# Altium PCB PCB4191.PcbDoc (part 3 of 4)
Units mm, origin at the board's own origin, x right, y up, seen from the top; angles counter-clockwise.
Board outline 160 x 160 mm, 6 copper layers (Top Layer, IM1 RIS, IM2 Signal, IM3 Signal, IM4 GND, Bottom Layer), stack 1.582 mm thick; 143 components, 121 nets, 430 pads, 4960 vias.

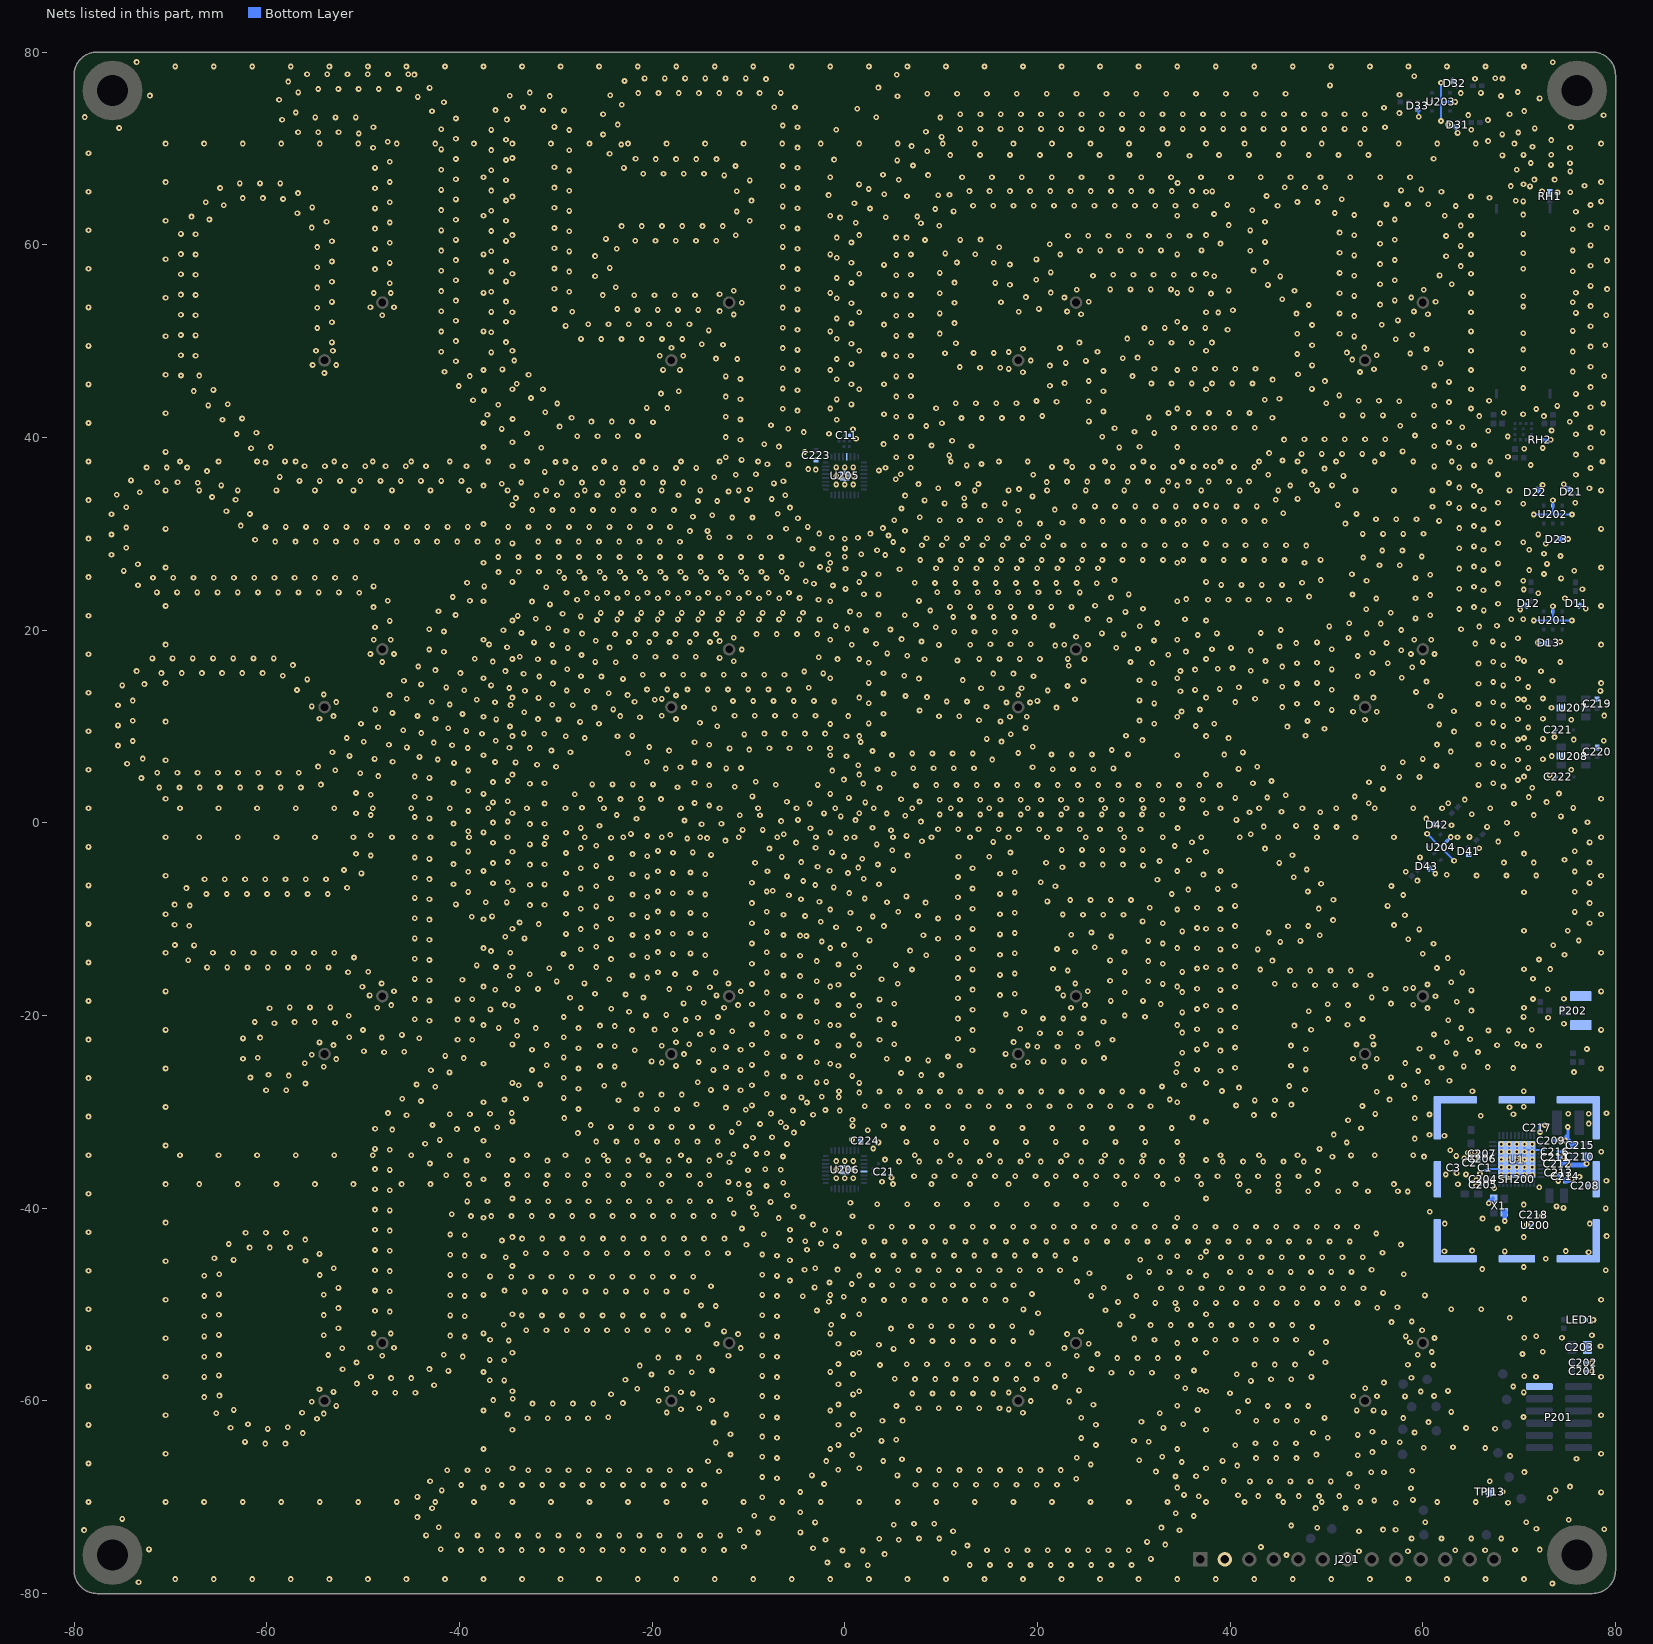
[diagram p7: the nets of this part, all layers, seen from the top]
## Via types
v1: diameter 0.6, hole 0.25, IM4 GND to Bottom Layer, tented bottom, 3930 vias
v2: diameter 0.6, hole 0.25, Top Layer to Bottom Layer, tented both sides, 851 vias
v3: diameter 0.6, hole 0.25, IM4 GND to Bottom Layer, tented both sides, 179 vias

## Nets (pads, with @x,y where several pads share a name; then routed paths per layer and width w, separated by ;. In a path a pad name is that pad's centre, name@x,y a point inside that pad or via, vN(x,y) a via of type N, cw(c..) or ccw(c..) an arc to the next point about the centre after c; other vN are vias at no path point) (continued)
GND: (continued)
  other v1: 0.276,-77.063 2.376,-77.063 12.972,-77.038 15.072,-77.038 17.172,-77.038 19.272,-77.038 21.372,-77.038 23.472,-77.038 25.572,-77.038 27.672,-77.038 29.772,-77.038 -1.804,-76.776 31.774,-76.405 45.849,-76 4.127,-75.903 11.306,-75.76 58.449,-75.616 53.368,-75.606 -0.231,-75.537 1.869,-75.537 14.763,-75.512 16.863,-75.512 18.963,-75.512 21.063,-75.512 23.163,-75.512 25.263,-75.512 27.363,-75.512 29.463,-75.512 63.363,-75.515 66.463,-75.515 -39.84,-75.488 -37.74,-75.488 -35.64,-75.488 -33.54,-75.488 -31.44,-75.488 -29.34,-75.488 -27.24,-75.488 -25.14,-75.488 -23.04,-75.488 -20.94,-75.488 -18.84,-75.488 -16.74,-75.488 -14.64,-75.488 -12.54,-75.488 69.562,-75.45 -41.939,-75.409 -3.289,-75.291 43.186,-75.174 -10.468,-75.148 12.722,-75.018 33.259,-74.921 31.376,-74.645 5.612,-74.418 -2.006,-74.414 3.568,-74.303 7.708,-74.288 9.808,-74.288 58.833,-74.286 61.933,-74.286 65.033,-74.286 68.133,-74.286 -43.464,-73.965 -40.222,-73.962 -38.122,-73.962 -36.022,-73.962 -33.922,-73.962 -31.822,-73.962 -29.722,-73.962 -27.622,-73.962 -25.522,-73.962 -23.422,-73.962 -21.322,-73.962 -19.222,-73.962 -17.122,-73.962 -15.022,-73.962 -12.922,-73.962 -8.983,-73.663 -4.611,-73.66 11.237,-73.533 53.375,-73.529 34.744,-73.436 -10.894,-73.415 55.873,-73.366 71.783,-73.287 32.861,-73.16 49.049,-73.166 -42.147,-73.123 46.351,-72.941 5.086,-72.852 7.184,-72.762 9.284,-72.762 -3.087,-72.614 70.733,-72.597 -7.498,-72.178 -44.363,-72.067 -9.409,-71.93 36.229,-71.951 34.346,-71.675 -4.613,-71.56 -42.837,-71.14 48.87,-71.135 51.97,-71.135 54.966,-70.339 -8.563,-70.008 -44.362,-69.967 36.738,-69.913 42.918,-69.888 45.018,-69.888 47.118,-69.888 49.218,-69.888 51.318,-69.888 40.82,-69.802 35.212,-69.762 -4.613,-69.46 -41.838,-69.293 58.768,-69.061 53.183,-68.922 -39.813,-68.738 -35.613,-68.738 -33.513,-68.738 -31.413,-68.738 -29.313,-68.738 -27.213,-68.738 -25.113,-68.738 -23.013,-68.738 -20.913,-68.738 -18.813,-68.738 -16.713,-68.738 7.326,-68.713 9.426,-68.713 11.526,-68.713 13.626,-68.713 15.726,-68.713 17.826,-68.713 19.926,-68.713 22.026,-68.713 -14.613,-68.701 -2.153,-68.633 42.048,-68.362 44.148,-68.362 46.248,-68.362 48.348,-68.362 50.448,-68.362 -43.04,-68.336 39.326,-68.326 24.033,-68.096 -7.037,-68.029 -8.563,-67.908 34.327,-67.857 36.461,-67.832 5.463,-67.743 -3.415,-67.735 52.388,-67.557 54.642,-67.412 55.96,-67.403 32.293,-67.338 -13.047,-67.302 -41.266,-67.212 -39.166,-67.212 -37.066,-67.212 -32.866,-67.212 -30.766,-67.212 -28.666,-67.212 -26.566,-67.212 -24.466,-67.212 -22.366,-67.212 -20.266,-67.212 -18.166,-67.212 -16.066,-67.212 7.706,-67.187 9.806,-67.187 11.906,-67.187 14.006,-67.187 16.106,-67.187 18.206,-67.187 20.306,-67.187 22.406,-67.187 -0.668,-67.148 40.738,-66.72 25.518,-66.611 34.976,-66.347 -14.184,-66.28 -1.93,-66.25 3.99,-66.247 39.212,-66.229 30.555,-66.159 5.936,-66.057 42.687,-65.938 44.787,-65.938 46.887,-65.938 -7.037,-65.929 24.068,-65.903 -8.563,-65.808 32.946,-65.812 53.237,-65.636 0.779,-65.626 -11.862,-65.568 48.955,-65.574 54.763,-65.315 40.537,-64.601 -0.663,-64.575 26.063,-64.583 -60.16,-64.438 -58.06,-64.438 42.629,-64.412 44.729,-64.412 46.829,-64.412 -13.388,-64.336 55.96,-64.303 -62.252,-64.257 31.538,-64.253 3.812,-64.154 30.012,-64.131 5.338,-64.044 24.537,-63.856 -7.037,-63.829 50.138,-63.839 -8.563,-63.708 0.863,-63.527 53.237,-63.536 -11.862,-63.468 -56.266,-63.346 48.612,-63.302 54.763,-63.215 -59.903,-62.912 33.067,-62.813 -63.747,-62.782 -57.811,-62.731 26.063,-62.483 -0.663,-62.475 -61.946,-62.425 35.131,-62.424 -13.629,-62.25 30.79,-62.18 3.904,-62.056 6.003,-62.052 42.716,-62.063 44.816,-62.063 46.916,-62.063 -54.781,-61.861 -32.94,-61.813 -30.84,-61.813 -28.74,-61.813 -26.64,-61.813 24.537,-61.756 49.796,-61.767 -7.037,-61.729 -24.543,-61.695 -8.563,-61.608 -12.305,-61.416 0.863,-61.427 -35,-61.405 -54.082,-61.32 -65.232,-61.297 32.691,-61.287 -56.326,-61.247 18.484,-61.237 -18.484,-61.213 55.96,-61.203 40.832,-61.136 53.137,-60.991 54.887,-60.991 -63.431,-60.94 36.616,-60.939 17.009,-60.887 -17.009,-60.863 -15.114,-60.765 7.661,-60.763 9.761,-60.763 11.861,-60.763 13.961,-60.763 16.061,-60.763 -52.792,-60.524 5.356,-60.539 43.895,-60.537 45.995,-60.537 48.095,-60.537 25.804,-60.399 -0.663,-60.375 -32.417,-60.287 -30.317,-60.287 -28.217,-60.287 -26.117,-60.287 -23.032,-60.237 -55.32,-60.082 23.302,-60.057 19.309,-60.012 41.862,-60.008 -19.309,-59.988 -36.485,-59.92 -13.79,-59.931 -34.457,-59.789 -66.488,-59.615 -7.037,-59.629 -8.563,-59.508 52.787,-59.516 55.237,-59.516 -64.916,-59.455 -24.26,-59.306 0.863,-59.327 -15.772,-59.237 7.003,-59.237 9.103,-59.237 11.203,-59.237 13.303,-59.237 15.403,-59.237 39.987,-59.214 -48.772,-59.163 -46.672,-59.163 -44.572,-59.163 17.009,-59.137 -17.009,-59.113 -53.075,-59.075 62.615,-58.966 24.319,-58.915 36.863,-58.854 -54.524,-58.792 18.484,-58.787 -21.547,-58.752 -18.484,-58.763 35.337,-58.689 54.012,-58.691 21.817,-58.572 -42.624,-58.379 -0.663,-58.275 -50.644,-58.211 55.96,-58.103 42.152,-57.928 -35.337,-57.882 -36.863,-57.854 -22.775,-57.821 44.245,-57.763 46.345,-57.763 7.29,-57.738 9.39,-57.738 11.49,-57.738 13.59,-57.738 15.69,-57.738 17.79,-57.738 19.89,-57.738 5.19,-57.702 -47.094,-57.637 -44.994,-57.637 58.809,-57.613 -7.037,-57.529 -66.488,-57.515 -49.19,-57.506 48.43,-57.514 22.834,-57.43 -8.563,-57.408 -64.962,-57.355 -20.063,-57.267 0.863,-57.227 40.687,-57.234 27.677,-57.088 29.777,-57.088 31.877,-57.088 -17.975,-57.038 -15.875,-57.038 -41.139,-56.894 -13.784,-56.847 36.25,-56.845 -52.129,-56.726 -43.111,-56.707 25.614,-56.694 -21.29,-56.336 3.65,-56.274 58.453,-56.26 61.069,-56.279 42.535,-56.237 44.635,-56.237 46.735,-56.237 6.423,-56.212 8.523,-56.212 10.623,-56.212 12.723,-56.212 14.823,-56.212 16.923,-56.212 19.023,-56.212 21.123,-56.212 -0.663,-56.175 -50.675,-56.021 49.882,-55.997 -35.337,-55.782 -36.863,-55.754 28.288,-55.562 30.388,-55.562 32.488,-55.562 34.588,-55.562 -19.359,-55.512 -17.259,-55.512 -15.159,-55.512 -7.037,-55.429 -66.488,-55.415 -39.656,-55.408 -12.082,-55.32 24.082,-55.32 -48.012,-55.309 -8.563,-55.308 -64.962,-55.255 -53.614,-55.241 -41.626,-55.222 59.476,-55.208 26.229,-55.149 0.863,-55.127 48.448,-55.023 60.925,-54.925 5.063,-54.612 -52.16,-54.536 -10.792,-54.524 22.792,-54.524 -49.237,-54.484 -46.787,-54.484 3.537,-54.177 -13.32,-54.082 -0.663,-54.075 25.32,-54.082 49.936,-53.897 58.68,-53.918 6.995,-53.788 9.095,-53.788 11.195,-53.788 13.295,-53.788 15.395,-53.788 17.495,-53.788 -34.878,-53.732 -36.819,-53.655 32.148,-53.663 36.348,-53.663 38.448,-53.663 40.548,-53.663 42.648,-53.663 44.748,-53.663 46.848,-53.663 30.052,-53.534 61.208,-53.476 74.438,-53.46 -66.488,-53.315 -39.437,-53.319 -7.037,-53.329 58.227,-53.307 71.78,-53.303 -40.963,-53.229 -54.088,-53.195 -8.563,-53.208 -64.962,-53.155 -11.075,-53.075 23.075,-53.075 -48.887,-53.009 -47.137,-53.009 0.863,-53.027 19.4,-52.904 -12.524,-52.792 24.524,-52.792 59.918,-52.68 -33.071,-52.663 -30.971,-52.663 -28.871,-52.663 -26.771,-52.663 -24.671,-52.663 -22.571,-52.663 -20.471,-52.663 -18.371,-52.663 -16.271,-52.663 4.798,-52.498 -52.562,-52.475 48.528,-52.339 6.884,-52.262 8.984,-52.262 11.084,-52.262 13.184,-52.262 15.284,-52.262 17.384,-52.262 31.738,-52.137 33.838,-52.137 35.938,-52.137 38.038,-52.137 40.138,-52.137 42.238,-52.137 44.338,-52.137 46.438,-52.137 -35.406,-52.101 -1.405,-52.111 28.543,-52.073 -14.258,-52.063 56.742,-51.822 58.841,-51.762 69.031,-51.378 -7.037,-51.229 -66.488,-51.215 -39.437,-51.219 29.849,-51.22 -0.162,-51.195 -40.963,-51.129 -33.541,-51.137 -31.441,-51.137 -29.341,-51.137 -27.241,-51.137 -25.141,-51.137 -23.041,-51.137 -20.941,-51.137 -18.841,-51.137 -16.741,-51.137 -8.563,-51.108 -54.088,-51.095 -64.962,-51.055 20.063,-50.912 -47.237,-50.731 -48.763,-50.647 -2.89,-50.626 27.058,-50.588 18.537,-50.506 62.958,-50.498 66.058,-50.498 -52.562,-50.375 55.257,-50.337 57.357,-50.277 -13.387,-50.152 -14.913,-50.102 32.217,-49.838 34.317,-49.838 36.417,-49.838 38.517,-49.838 40.617,-49.838 42.717,-49.838 44.817,-49.838 46.917,-49.838 49.017,-49.838 51.117,-49.838 53.217,-49.838 28.364,-49.735 -1.647,-49.71 1.973,-49.538 4.073,-49.538 6.173,-49.538 8.273,-49.538 10.373,-49.538 12.473,-49.538 14.573,-49.538 16.673,-49.538 -0.1,-49.204 -39.437,-49.119 -7.037,-49.129 -4.375,-49.141 30.243,-49.123 -66.488,-49.115 25.574,-49.103 60.212,-49.06 -40.963,-49.029 -54.088,-48.995 -8.563,-49.008 -64.962,-48.955 19.418,-48.913 55.872,-48.792 -33.219,-48.638 -31.119,-48.638 -29.019,-48.638 -26.919,-48.638 -24.819,-48.638 -22.719,-48.638 -20.619,-48.638 -18.519,-48.638 -16.419,-48.638 -47.237,-48.631 -48.763,-48.547 -35.318,-48.557 32.827,-48.312 34.927,-48.312 37.027,-48.312 39.127,-48.312 41.227,-48.312 43.327,-48.312 45.427,-48.312 47.527,-48.312 49.627,-48.312 51.727,-48.312 53.827,-48.312 -52.562,-48.275 26.879,-48.25 -3.132,-48.225 -13.884,-48.112 2.821,-48.012 4.921,-48.012 7.021,-48.012 9.121,-48.012 11.221,-48.012 13.321,-48.012 15.421,-48.012 17.521,-48.012 0.726,-47.872 -1.585,-47.719 24.089,-47.618 -5.698,-47.51 29.562,-47.136 -34.63,-47.112 -32.53,-47.112 -30.43,-47.112 -28.33,-47.112 -26.23,-47.112 -24.13,-47.112 -22.03,-47.112 -19.93,-47.112 -17.83,-47.112 -15.73,-47.112 -36.812,-47.082 -66.488,-47.015 -39.437,-47.019 -7.037,-47.029 -54.495,-46.935 -40.963,-46.929 -8.563,-46.908 58.02,-46.868 -64.926,-46.856 25.394,-46.765 31.592,-46.613 33.692,-46.613 35.792,-46.613 39.992,-46.613 42.092,-46.613 44.192,-46.613 46.292,-46.613 48.392,-46.613 50.492,-46.613 52.592,-46.613 -47.237,-46.531 -48.763,-46.447 3.451,-46.438 5.551,-46.438 7.651,-46.438 9.751,-46.438 11.851,-46.438 13.951,-46.438 16.051,-46.438 18.151,-46.438 20.251,-46.438 22.351,-46.438 -4.173,-46.401 -0.748,-46.376 54.681,-46.396 -53.04,-46.23 -3.07,-46.234 -55.98,-45.45 -5.7,-45.41 -63.441,-45.371 30.669,-45.352 23.909,-45.28 72.752,-45.249 -65.43,-45.201 -35.181,-45.085 32.752,-45.087 36.952,-45.087 39.052,-45.087 41.152,-45.087 43.252,-45.087 45.352,-45.087 47.452,-45.087 49.552,-45.087 51.652,-45.087 53.752,-45.087 -7.037,-44.929 -39.437,-44.919 0.842,-44.912 2.942,-44.912 5.042,-44.912 7.142,-44.912 9.242,-44.912 11.342,-44.912 13.442,-44.912 15.542,-44.912 17.642,-44.912 19.742,-44.912 21.842,-44.912 -40.963,-44.829 -8.563,-44.808 -54.525,-44.745 -33.118,-44.688 -31.018,-44.688 -28.918,-44.688 -26.818,-44.688 -24.718,-44.688 -22.618,-44.688 -20.518,-44.688 -18.418,-44.688 -16.318,-44.688 -14.218,-44.688 -12.119,-44.688 55.813,-44.627 -47.237,-44.431 -48.763,-44.347 -3.924,-44.316 -61.778,-44.088 -59.678,-44.088 -57.578,-44.088 -0.925,-43.95 -10.214,-43.804 57.727,-43.782 -63.945,-43.716 2.02,-43.463 4.12,-43.463 6.22,-43.463 8.32,-43.463 10.42,-43.463 12.52,-43.463 14.62,-43.463 16.72,-43.463 18.82,-43.463 20.92,-43.463 23.02,-43.463 25.12,-43.463 27.22,-43.463 29.32,-43.463 31.42,-43.463 33.52,-43.463 35.62,-43.463 37.72,-43.463 39.82,-43.463 41.92,-43.463 44.02,-43.463 46.12,-43.463 48.22,-43.463 50.32,-43.463 52.42,-43.463 -35.591,-43.353 -5.7,-43.31 -56.01,-43.26 -33.5,-43.162 -31.4,-43.162 -29.3,-43.162 -27.2,-43.162 -25.1,-43.162 -23,-43.162 -20.9,-43.162 -18.8,-43.162 -16.7,-43.162 -14.6,-43.162 -12.5,-43.162 -39.437,-42.819 -40.963,-42.729 -8.417,-42.713 55.161,-42.631 -62.191,-42.562 -60.091,-42.562 -57.991,-42.562 -47.237,-42.331 -48.763,-42.247 -10.681,-42.112 67.747,-42.114 2.779,-41.937 4.879,-41.937 6.979,-41.937 9.079,-41.937 11.179,-41.937 13.279,-41.937 15.379,-41.937 17.479,-41.937 19.579,-41.937 21.679,-41.937 23.779,-41.937 25.879,-41.937 27.979,-41.937 30.079,-41.937 32.179,-41.937 34.279,-41.937 36.379,-41.937 38.479,-41.937 40.579,-41.937 42.679,-41.937 44.779,-41.937 46.879,-41.937 48.979,-41.937 51.079,-41.937 53.179,-41.937 -38.797,-40.819 -36.697,-40.819 -34.597,-40.819 -32.497,-40.819 -30.397,-40.819 -28.297,-40.819 -26.197,-40.819 -24.097,-40.819 -21.997,-40.819 -19.897,-40.819 -17.797,-40.819 -15.697,-40.819 -13.597,-40.819 -40.806,-40.635 -9.196,-40.627 -11.515,-40.544 60.716,-40.361 -47.237,-40.231 -48.763,-40.147 -9.518,-39.895 3.378,-39.594 6.478,-39.594 9.578,-39.594 12.678,-39.594 15.778,-39.594 18.878,-39.594 21.978,-39.594 25.078,-39.594 28.178,-39.594 31.278,-39.594 -39.19,-39.294 -37.09,-39.293 -32.89,-39.293 -30.79,-39.293 -28.69,-39.293 -26.59,-39.293 -24.49,-39.293 -22.39,-39.293 -20.29,-39.293 -18.19,-39.293 -16.09,-39.293 -13.99,-39.293 -11.902,-39.065 -9.905,-38.416 58.43,-38.267 41.911,-38.246 45.011,-38.246 48.111,-38.246 51.211,-38.246 54.311,-38.246 57.411,-38.246 -47.237,-38.131 -48.763,-38.047 -10.001,-37.6 -12.076,-37.278 7.197,-36.695 9.297,-36.695 11.397,-36.695 13.497,-36.695 15.597,-36.695 17.697,-36.695 19.797,-36.695 21.897,-36.695 23.997,-36.695 26.097,-36.695 28.197,-36.695 30.297,-36.695 32.397,-36.695 36.597,-36.695 38.697,-36.695 40.797,-36.695 42.897,-36.695 44.997,-36.695 47.097,-36.695 -41.36,-36.588 -39.26,-36.588 -35.06,-36.588 -32.96,-36.588 -30.86,-36.588 -28.76,-36.588 -26.66,-36.588 -24.56,-36.588 -22.46,-36.588 -20.36,-36.588 -18.26,-36.588 -16.16,-36.588 -14.06,-36.588 49.126,-36.154 -10.05,-36.073 -47.237,-36.031 -48.763,-35.947 -43.066,-35.364 -11.977,-35.24 5.637,-35.168 7.737,-35.168 9.837,-35.168 11.937,-35.168 14.037,-35.168 16.137,-35.168 18.237,-35.168 20.337,-35.168 22.437,-35.168 24.537,-35.168 26.637,-35.168 28.737,-35.168 30.837,-35.168 32.937,-35.168 35.037,-35.168 39.237,-35.168 41.337,-35.168 43.437,-35.168 45.537,-35.168 47.637,-35.168 -39.27,-35.062 -30.87,-35.062 -26.67,-35.062 -24.57,-35.062 -22.47,-35.062 -20.37,-35.062 -18.27,-35.062 -16.17,-35.062 -14.07,-35.062 50.611,-34.669 60.119,-34.644 -11.567,-34.413 -47.237,-33.931 -48.763,-33.847 49.271,-33.849 -10.254,-33.566 -43.563,-33.324 3.5,-33.175 52.096,-33.184 6.396,-33.123 9.496,-33.123 12.596,-33.123 15.696,-33.123 18.796,-33.123 21.896,-33.123 24.996,-33.123 28.096,-33.123 31.196,-33.123 -25.797,-33.088 -23.697,-33.088 -21.597,-33.088 -19.497,-33.088 -17.397,-33.088 -15.297,-33.088 -13.197,-33.088 -42.037,-32.917 59.164,-32.774 -9.533,-32.682 50.756,-32.364 60.69,-32.375 -27.701,-32.203 -11.739,-32.081 2.391,-31.917 -46.969,-31.848 -40.266,-31.788 -38.166,-31.788 -48.753,-31.747 53.581,-31.699 6.038,-31.677 9.138,-31.677 12.238,-31.677 15.338,-31.677 18.438,-31.677 21.538,-31.677 24.638,-31.677 27.738,-31.677 30.838,-31.677 33.938,-31.677 -36.074,-31.607 -6.112,-31.59 -24.274,-31.562 -22.174,-31.562 -20.074,-31.562 -17.974,-31.562 -15.874,-31.562 -13.774,-31.562 4.06,-31.447 -42.798,-31.368 -26.366,-31.38 -8.79,-31.266 -11.018,-31.197 52.241,-30.879 0.785,-30.819 -29.118,-30.653 59.164,-30.674 36.09,-30.595 66.011,-30.408 -45.484,-30.363 42.461,-30.338 44.561,-30.338 60.69,-30.275 -41.013,-30.262 -38.913,-30.262 -36.813,-30.209 55.066,-30.214 -7.668,-30.18 -47.411,-30.132 -34.578,-30.133 -10.275,-29.781 -21.619,-29.738 -19.519,-29.738 -17.419,-29.738 -27.637,-29.708 -12.338,-29.563 4.445,-29.413 6.545,-29.413 8.645,-29.413 10.745,-29.413 12.845,-29.413 14.945,-29.413 17.045,-29.413 19.145,-29.413 21.245,-29.413 23.345,-29.413 25.445,-29.413 27.545,-29.413 29.645,-29.413 31.745,-29.413 53.726,-29.394 40.612,-29.342 -9.638,-29.332 46.356,-29.249 -15.385,-29.215 -43.999,-28.878 42.545,-28.812 44.645,-28.801 -23.492,-28.788 -35.328,-28.724 33.729,-28.725 56.551,-28.729 -45.926,-28.647 -33.093,-28.648 59.164,-28.574 -29.163,-28.554 -4.503,-28.503 -6.362,-28.448 -21.117,-28.212 -19.017,-28.212 -16.917,-28.212 -8.112,-28.128 1.497,-28.002 3.594,-27.887 5.694,-27.887 7.794,-27.887 9.894,-27.887 11.994,-27.887 14.094,-27.887 16.194,-27.887 18.294,-27.887 20.394,-27.887 22.494,-27.887 24.594,-27.887 26.694,-27.887 28.794,-27.887 30.894,-27.887 55.211,-27.909 -0.598,-27.863 65.141,-27.87 39.144,-27.84 -60.064,-27.761 -57.964,-27.763 -10.812,-27.751 -13.9,-27.73 47.782,-27.707 -27.637,-27.608 40.916,-27.486 -12.338,-27.463 -42.514,-27.393 32.929,-27.367 -24.977,-27.303 46.13,-27.316 -33.843,-27.239 -9.638,-27.232 35.214,-27.24 58.035,-27.244 -22.944,-27.176 -44.441,-27.162 -31.608,-27.163 -55.984,-27.063 -2.911,-26.951 -15.256,-26.927 -1.918,-26.895 60.454,-26.917 62.757,-26.772 -29.163,-26.454 -61.693,-26.436 56.696,-26.424 -4.636,-26.407 -6.362,-26.348 0.778,-26.276 -57.714,-26.237 7.936,-26.188 10.036,-26.188 -59.813,-26.158 -8.112,-26.028 5.847,-25.973 -41.029,-25.908 34.413,-25.882 75.686,-25.879 59.52,-25.759 38.987,-25.746 -42.956,-25.677 -32.463,-25.656 -10.812,-25.651 -13.637,-25.646 36.554,-25.623 47.838,-25.608 -27.637,-25.508 69.39,-25.458 40.513,-25.425 61.938,-25.432 -12.338,-25.363 66.726,-25.36 -54.082,-25.32 -23.887,-25.3 53.988,-25.309 64.242,-25.287 -25.413,-25.249 -17.516,-25.237 11.903,-25.227 46.312,-25.224 -0.663,-25.211 17.516,-25.213 -30.937,-25.173 -9.638,-25.132 -56.044,-24.964 58.181,-24.94 -18.991,-24.887 18.991,-24.863 -2.911,-24.851 -15.163,-24.829 -20.055,-24.763 20.635,-24.763 22.735,-24.763 24.835,-24.763 8.653,-24.662 -52.792,-24.524 6.558,-24.528 -62.463,-24.482 4.36,-24.49 52.763,-24.484 55.213,-24.484 -39.544,-24.424 26.907,-24.423 -60.937,-24.384 -29.163,-24.354 -4.636,-24.307 10.714,-24.257 61.005,-24.274 -6.362,-24.248 -41.471,-24.192 0.863,-24.178 -55.32,-24.082 -16.691,-24.012 16.691,-23.988 -8.112,-23.928 63.423,-23.947 35.037,-23.877 -47.818,-23.813 65.727,-23.803 -45.718,-23.772 -49.915,-23.706 38.987,-23.646 -21.804,-23.601 13.25,-23.616 -32.463,-23.556 -13.657,-23.547 -10.812,-23.551 36.563,-23.523 47.838,-23.508 59.666,-23.455 -27.637,-23.408 40.513,-23.325 -12.338,-23.263 19.977,-23.237 22.077,-23.237 24.177,-23.237 -23.887,-23.2 -25.413,-23.149 -18.991,-23.137 -0.663,-23.111 18.991,-23.113 46.312,-23.124 67.702,-23.088 -53.075,-23.075 -30.937,-23.073 -9.638,-23.032 53.113,-23.009 54.863,-23.009 -16.153,-22.976 5.138,-22.98 69.796,-22.939 26.253,-22.918 -54.524,-22.792 -17.516,-22.787 62.49,-22.789 17.516,-22.763 -2.911,-22.751 -40.188,-22.529 3.612,-22.528 -38.662,-22.518 27.788,-22.516 64.908,-22.462 11.737,-22.423 -62.463,-22.382 -44.16,-22.364 -60.693,-22.298 -48.058,-22.287 -51.429,-22.251 -29.163,-22.254 -4.636,-22.207 54.763,-22.198 -6.362,-22.148 -33.989,-22.113 0.863,-22.078 -45.975,-22.02 61.151,-21.97 -15.021,-21.95 -8.112,-21.828 20.251,-21.838 22.351,-21.838 24.451,-21.838 35.037,-21.777 -13.761,-21.719 -11.681,-21.639 66.805,-21.562 68.905,-21.562 38.987,-21.546 -50.009,-21.511 -22.082,-21.519 13.263,-21.516 -17.638,-21.492 -19.738,-21.463 48.396,-21.483 71.3,-21.472 36.563,-21.423 18.202,-21.381 -32.082,-21.313 -27.637,-21.308 -35.919,-21.285 63.975,-21.304 40.513,-21.225 -23.871,-21.1 46.667,-21.054 -25.413,-21.049 -0.663,-21.011 52.185,-20.964 -9.638,-20.932 5.138,-20.88 -59.209,-20.813 -52.914,-20.766 -61.234,-20.68 -57.112,-20.688 -55.012,-20.688 -2.911,-20.651 26.845,-20.64 -34.053,-20.587 -43.112,-20.545 62.636,-20.485 -16.506,-20.465 -40.188,-20.429 -38.662,-20.418 3.612,-20.428 -44.638,-20.4 50.172,-20.363 53.742,-20.363 11.737,-20.323 20.571,-20.312 22.671,-20.312 24.771,-20.312 73.001,-20.242 -15.246,-20.234 -29.163,-20.154 -13.166,-20.154 70.461,-20.152 31.157,-20.137 -4.636,-20.107 -6.362,-20.048 -51.494,-20.026 -20.638,-19.995 29.062,-19.999 0.863,-19.978 -18.538,-19.937 16.717,-19.896 -8.112,-19.728 35.037,-19.677 -22.386,-19.615 18.591,-19.611 48.151,-19.569 65.038,-19.493 38.987,-19.446 13.263,-19.416 -36.788,-19.374 -24.238,-19.309 36.563,-19.323 -59.707,-19.238 60.484,-19.237 -48.524,-19.208 -27.415,-19.22 -12.524,-19.208 23.476,-19.208 -57.608,-19.162 -55.508,-19.162 -53.408,-19.162 40.513,-19.125 -47.075,-18.925 -11.075,-18.925 24.925,-18.925 -0.663,-18.911 52.218,-18.918 -35.262,-18.87 59.009,-18.887 -9.638,-18.832 50.12,-18.837 32.789,-18.815 5.138,-18.78 -16.731,-18.749 56.694,-18.763 -14.651,-18.669 63.512,-18.576 -2.911,-18.551 27.605,-18.487 30.957,-18.489 -43.112,-18.445 -40.188,-18.329 -38.662,-18.318 3.612,-18.328 -44.638,-18.3 71.432,-18.289 11.737,-18.223 -28.512,-18.157 -20.901,-18.13 54.694,-18.123 -4.636,-18.007 61.309,-18.012 -6.362,-17.948 -49.32,-17.918 -13.32,-17.918 22.68,-17.918 0.863,-17.878 16.112,-17.885 -22.753,-17.824 -25.93,-17.735 17.638,-17.74 -8.112,-17.628 29.063,-17.58 35.037,-17.577 -46.792,-17.476 -10.792,-17.476 25.208,-17.476 65.038,-17.393 38.987,-17.346 -36.289,-17.334 13.263,-17.316 72.959,-17.269 -18.216,-17.264 -33.939,-17.238 -31.839,-17.238 36.563,-17.223 56.118,-17.237 58.218,-17.237 22.117,-17.197 -16.136,-17.185 59.009,-17.137 -14.005,-17.075 40.513,-17.025 -50.071,-17.008 46.714,-16.863 48.814,-16.863 50.914,-16.863 53.014,-16.863 -0.663,-16.811 60.484,-16.787 -9.638,-16.732 5.494,-16.711 33.013,-16.727 44.62,-16.696 -48.082,-16.68 -27.027,-16.672 -12.082,-16.68 23.918,-16.68 62.949,-16.553 -29.887,-16.466 31.487,-16.457 -2.911,-16.451 27.537,-16.388 -43.112,-16.345 -39.693,-16.289 -24.453,-16.242 3.817,-16.238 -44.638,-16.2 71.432,-16.189 11.737,-16.123 -20.512,-16.067 -4.636,-15.907 -34.787,-15.866 -22.038,-15.849 -6.362,-15.848 54.559,-15.83 0.863,-15.778 16.112,-15.785 -32.692,-15.712 -17.621,-15.7 17.638,-15.64 -15.49,-15.59 -51.556,-15.523 -19.388,-15.522 -13.391,-15.53 -8.112,-15.528 64.079,-15.525 29.063,-15.48 35.037,-15.477 -49.457,-15.463 23.138,-15.335 46.218,-15.337 48.318,-15.337 50.418,-15.337 52.518,-15.337 38.987,-15.246 6.979,-15.226 13.263,-15.216 43.121,-15.226 73.219,-15.185 21.612,-15.159 36.563,-15.123 -30.683,-15.103 61.464,-15.068 -66.193,-15.013 -64.093,-15.013 -61.993,-15.013 -59.893,-15.013 -57.793,-15.013 -55.693,-15.013 -53.593,-15.013 -36.213,-14.967 -28.402,-14.981 -25.788,-14.977 40.513,-14.925 -38.208,-14.804 5.297,-14.748 -0.663,-14.711 -9.638,-14.632 33.013,-14.627 -2.911,-14.351 31.487,-14.357 44.388,-14.306 -68.158,-14.271 27.537,-14.288 -43.112,-14.245 72.06,-14.185 -24.262,-14.151 -44.638,-14.1 11.737,-14.023 62.595,-14.04 -50.942,-13.978 -20.512,-13.967 -4.636,-13.807 -22.038,-13.749 -14.487,-13.739 -6.362,-13.748 8.464,-13.741 1.089,-13.69 74.704,-13.7 16.112,-13.685 -29.198,-13.618 -17.862,-13.613 59.979,-13.583 -16.013,-13.556 17.638,-13.54 -65.584,-13.487 -63.484,-13.487 -61.384,-13.487 -59.284,-13.487 -57.184,-13.487 -55.084,-13.487 -52.984,-13.487 -34.728,-13.482 -19.388,-13.422 -8.112,-13.428 23.901,-13.378 29.035,-13.381 -36.723,-13.319 6.782,-13.263 -27.412,-13.129 38.987,-13.146 42.862,-13.142 13.263,-13.116 22.022,-13.099 36.563,-13.023 25.949,-12.913 -25.788,-12.877 40.513,-12.825 -67.542,-12.729 73.545,-12.701 -69.536,-12.687 -0.074,-12.695 61.11,-12.555 -9.638,-12.532 33.013,-12.527 45.189,-12.365 -2.388,-12.317 31.487,-12.257 47.287,-12.263 76.189,-12.215 2.574,-12.205 -43.112,-12.145 58.494,-12.098 -24.262,-12.051 9.688,-12.035 -44.638,-12 -33.243,-11.997 11.737,-11.923 -20.512,-11.867 -35.238,-11.834 27.653,-11.799 -3.983,-11.754 -4.636,-11.707 8.162,-11.68 49.303,-11.676 -22.038,-11.649 -14.487,-11.639 -6.362,-11.648 23.507,-11.614 16.112,-11.585 -28.938,-11.534 -17.862,-11.513 -16.013,-11.456 17.638,-11.44 25.594,-11.387 44.011,-11.384 -8.112,-11.328 -19.388,-11.322 35.037,-11.277 75.03,-11.216 59.625,-11.07 38.987,-11.046 -27.412,-11.029 13.263,-11.016 36.563,-10.923 -0.903,-10.832 -25.788,-10.777 4.059,-10.72 40.513,-10.725 46.009,-10.737 48.109,-10.712 -68.037,-10.688 57.009,-10.613 -69.563,-10.587 -31.758,-10.513 77.304,-10.436 -9.638,-10.432 32.999,-10.427 -33.753,-10.349 -2.498,-10.269 30.909,-10.238 50.685,-10.094 -43.112,-10.045 -24.262,-9.951 9.688,-9.935 -44.638,-9.9 11.737,-9.823 -38.71,-9.763 -20.512,-9.767 2.895,-9.725 -36.61,-9.714 -4.118,-9.672 7.601,-9.656 58.14,-9.585 -22.038,-9.549 -6.362,-9.548 -14.487,-9.539 24.729,-9.538 26.829,-9.538 28.929,-9.538 22.629,-9.519 16.112,-9.485 -28.938,-9.434 -17.862,-9.413 -16.013,-9.356 0.582,-9.348 17.638,-9.34 75.778,-9.253 -19.388,-9.222 -8.112,-9.228 5.544,-9.235 38.987,-8.946 -27.412,-8.929 13.263,-8.916 49.187,-8.91 31.649,-8.819 36.563,-8.823 -25.788,-8.677 40.513,-8.625 56.337,-8.624 -67.984,-8.588 -32.688,-8.539 -69.563,-8.487 -31.162,-8.499 -40.362,-8.467 -9.638,-8.332 77.304,-8.336 8.389,-8.285 -35.092,-8.263 -37.276,-8.237 4.38,-8.24 -2.633,-8.187 21.029,-8.159 23.41,-8.012 25.51,-8.012 27.61,-8.012 29.71,-8.012 50.713,-7.995 -43.112,-7.945 -4.547,-7.942 -24.262,-7.851 2.067,-7.863 -44.638,-7.8 11.737,-7.723 -20.512,-7.667 6.392,-7.637 -5.796,-7.526 57.964,-7.493 -22.038,-7.449 -14.487,-7.439 -66.26,-7.388 -64.161,-7.388 -62.061,-7.388 -59.961,-7.388 -57.861,-7.388 -55.761,-7.388 -53.661,-7.388 33.935,-7.389 16.112,-7.385 -28.938,-7.334 -17.862,-7.313 0.471,-7.299 -16.013,-7.256 17.638,-7.24 -39.087,-7.174 75.778,-7.153 -19.388,-7.122 -8.112,-7.128 48.074,-7.129 -7.482,-7.052 35.641,-6.936 38.71,-6.865 -27.412,-6.829 13.263,-6.816 -68.337,-6.782 -51.662,-6.742 -1.148,-6.702 -25.788,-6.577 21.863,-6.591 56.736,-6.562 40.44,-6.527 -3.062,-6.457 -32.688,-6.439 -31.162,-6.399 -40.613,-6.383 3.552,-6.378 49.434,-6.329 -36.513,-6.28 -9.638,-6.232 77.304,-6.236 20.337,-6.176 -34.987,-6.166 -4.311,-6.041 59.437,-5.996 32.45,-5.904 -66.449,-5.862 -64.349,-5.862 -62.249,-5.862 -60.149,-5.862 -58.049,-5.862 -55.949,-5.862 -53.849,-5.862 -43.112,-5.845 1.956,-5.814 -24.262,-5.751 -44.638,-5.7 46.589,-5.644 11.737,-5.623 -20.512,-5.567 -5.997,-5.567 65.581,-5.469 68.681,-5.469 71.781,-5.469 62.482,-5.384 37.225,-5.38 -22.038,-5.349 -14.487,-5.339 16.112,-5.285 -50.178,-5.257 -28.938,-5.234 -17.862,-5.213 0.337,-5.217 -16.013,-5.156 17.638,-5.14 58.221,-5.077 -39.087,-5.074 75.778,-5.053 -8.025,-5.029 -19.388,-5.022 39.001,-4.997 -1.577,-4.972 -51.981,-4.902 5.037,-4.893 47.949,-4.844 -27.412,-4.729 13.263,-4.716 22.585,-4.619 -2.826,-4.556 -25.788,-4.477 30.965,-4.419 -32.688,-4.339 3.441,-4.329 24.666,-4.338 26.766,-4.338 28.866,-4.338 -31.162,-4.299 -40.613,-4.283 -36.513,-4.18 -9.312,-4.157 20.894,-4.151 45.104,-4.159 77.304,-4.136 68.417,-4.131 71.517,-4.131 -34.987,-4.066 -4.512,-4.082 32.671,-3.966 35.74,-3.895 74.701,-3.843 -43.112,-3.745 1.822,-3.733 -24.262,-3.651 -44.638,-3.6 59.706,-3.592 -6.54,-3.545 11.811,-3.524 14.985,-3.513 -0.092,-3.488 -20.512,-3.467 6.522,-3.408 -49.212,-3.392 46.464,-3.36 -13.875,-3.33 -22.038,-3.249 -50.738,-3.21 -28.938,-3.134 -17.834,-3.114 -15.774,-3.07 -1.342,-3.071 17.192,-3.088 -39.087,-2.974 75.778,-2.953 -19.388,-2.922 4.926,-2.844 22.517,-2.818 24.617,-2.812 26.717,-2.812 28.817,-2.812 30.917,-2.812 -7.827,-2.672 43.619,-2.674 65.836,-2.637 -27.412,-2.629 -3.027,-2.598 34.255,-2.41 -25.788,-2.377 -32.688,-2.239 3.307,-2.248 -40.613,-2.183 -31.162,-2.199 -36.513,-2.08 -5.055,-2.06 77.304,-2.036 36.032,-2.027 15.404,-1.987 67.821,-1.952 8.007,-1.923 -12.39,-1.845 -16.349,-1.629 -14.289,-1.585 0.143,-1.586 -24.262,-1.551 -44.638,-1.5 64.846,-1.468 -20.512,-1.367 6.411,-1.359 -49.212,-1.292 -18.124,-1.245 -6.342,-1.187 42.134,-1.189 -22.199,-1.155 69.752,-1.127 -28.938,-1.034 -39.087,-0.874 75.778,-0.853 4.792,-0.763 -10.605,-0.738 -8.505,-0.738 9.687,-0.663 11.787,-0.663 13.887,-0.663 15.987,-0.663 18.087,-0.663 20.187,-0.663 22.287,-0.663 24.387,-0.663 26.487,-0.663 28.587,-0.663 30.687,-0.663 -3.57,-0.575 -27.412,-0.529 34.547,-0.542 2.878,-0.518 48.941,-0.438 51.041,-0.438 66.669,-0.426 43.494,-0.39 -25.457,-0.303 46.844,-0.321 -32.688,-0.139 -14.864,-0.144 -31.162,-0.099 -12.804,-0.1 -40.613,-0.083 68.725,0.004 -36.513,0.02 77.094,0.054 7.896,0.126 -34.987,0.134 -6.616,0.179 -16.639,0.24 1.113,0.277 -4.857,0.298 40.65,0.296 -21.616,0.42 -43.112,0.455 52.897,0.543 -44.638,0.6 -0.413,0.658 74.329,0.667 6.277,0.722 -10.901,0.788 -8.801,0.788 -49.212,0.808 -23.678,0.813 32.962,0.836 9.862,0.863 11.962,0.863 14.062,0.863 16.162,0.863 18.262,0.863 20.362,0.863 22.462,0.863 24.562,0.863 26.662,0.863 28.762,0.863 30.862,0.863 65.083,0.877 4.363,0.967 -50.738,0.99 -2.156,0.978 42.009,1.095 49.346,1.088 45.333,1.138 -39.087,1.226 75.612,1.542 -27.279,1.567 -14.062,1.797 69.462,1.971 -31.162,2.001 -3.638,2.008 54.382,2.028 -15.588,2.058 -36.513,2.12 2.123,2.118 72.844,2.152 -6.012,2.19 7.762,2.207 -34.987,2.234 9.854,2.387 11.954,2.387 14.054,2.387 16.154,2.387 18.254,2.387 20.354,2.387 22.454,2.387 24.554,2.387 26.654,2.387 28.754,2.387 30.854,2.387 32.954,2.387 35.054,2.387 37.154,2.387 64.344,2.403 -25.379,2.462 -23.279,2.462 -21.179,2.462 -19.079,2.462 5.848,2.452 -43.112,2.555 0.428,2.582 40.524,2.58 43.848,2.623 70.988,2.67 -44.638,2.7 -9.585,2.737 52.925,2.729 45.779,2.85 -49.212,2.908 -28.04,2.964 74.127,3.027 -50.738,3.09 -39.087,3.326 55.867,3.513 3.607,3.603 71.359,3.637 -71.154,3.662 -69.054,3.662 -66.954,3.662 -64.854,3.662 -62.754,3.662 -60.654,3.662 -58.554,3.662 -56.454,3.662 -17.367,3.678 -11.426,3.746 68.364,3.761 7.398,3.868 -14.062,3.897 9.498,3.913 11.598,3.913 13.698,3.913 15.798,3.913 17.898,3.913 19.998,3.913 22.098,3.913 24.198,3.913 26.298,3.913 28.398,3.913 30.498,3.913 32.598,3.913 34.698,3.913 36.798,3.913 38.898,3.909 -2.797,3.932 65.787,3.929 -7.165,3.945 -54.377,3.969 -26.207,3.988 -24.107,3.988 -22.007,3.988 -19.907,3.988 -32.688,4.061 1.913,4.067 -40.613,4.117 -31.162,4.101 42.363,4.107 67.313,4.115 -15.588,4.158 -36.513,4.22 54.41,4.214 -9.241,4.263 -34.987,4.334 44.294,4.335 69.863,4.444 -0.09,4.481 -73.006,4.652 -43.112,4.655 57.555,4.762 59.655,4.762 -44.638,4.8 -48.418,4.852 5.092,5.088 -50.288,5.142 -71.372,5.188 -69.272,5.188 -67.172,5.188 -65.072,5.188 -62.972,5.188 -60.872,5.188 -58.772,5.188 -56.672,5.188 -39.087,5.426 -1.312,5.417 -52.892,5.453 3.398,5.552 21.586,5.562 23.686,5.562 25.786,5.562 40.878,5.592 -18.588,5.623 -12.313,5.65 7.112,5.662 9.212,5.662 11.312,5.662 13.412,5.662 27.884,5.65 -10.787,5.685 70.937,5.694 55.895,5.699 -17.062,5.756 19.495,5.762 42.809,5.82 -54.673,5.831 -29.967,5.828 68.337,5.861 61.414,5.91 1.395,5.966 -14.062,5.997 -31.934,6.021 65.787,6.029 -74.491,6.137 -40.563,6.217 67.313,6.215 -34.175,6.271 -15.588,6.258 57.911,6.288 -36.294,6.309 -46.934,6.337 -20.563,6.337 15.312,6.557 69.863,6.544 -42.25,6.57 72.463,6.604 -48.803,6.626 59.982,6.636 -72.863,6.667 -44.14,6.84 0.173,6.902 -51.407,6.938 4.897,7.023 21.453,7.088 23.553,7.088 25.653,7.088 39.393,7.077 29.403,7.099 6.991,7.188 9.091,7.188 11.191,7.188 13.291,7.188 -22.47,7.216 18.005,7.241 -53.188,7.316 -28.482,7.313 41.325,7.305 62.899,7.394 2.88,7.45 -18.24,7.494 -30.449,7.506 27.7,7.555 -9.922,7.599 -11.96,7.72 -7.826,7.737 -5.726,7.737 -3.626,7.737 -1.526,7.737 -39.142,7.763 -32.69,7.756 -34.81,7.794 70.937,7.794 -45.449,7.822 -20.307,7.863 19.513,7.892 68.337,7.961 -75.438,8.011 -40.765,8.055 -14.062,8.097 -47.318,8.111 61.466,8.121 65.787,8.129 -42.655,8.324 67.313,8.315 -15.588,8.358 1.657,8.387 -49.922,8.423 16.263,8.43 -73.912,8.487 -36.238,8.508 30.888,8.584 69.863,8.644 14.737,8.711 72.463,8.704 39.84,8.79 -51.703,8.801 -26.997,8.798 -28.964,8.991 -23.588,8.993 0.163,8.984 -22.062,9.017 29.185,9.04 47.815,9.037 -10.442,9.172 17.237,9.196 4.013,9.218 -37.657,9.247 -31.205,9.241 -8.344,9.263 -6.244,9.263 -4.144,9.263 -2.044,9.263 -33.325,9.279 -43.964,9.307 63.238,9.467 -39.28,9.54 -45.833,9.596 49.788,9.758 -41.17,9.809 18.763,9.854 -48.437,9.908 70.937,9.894 45.94,9.981 -34.753,9.993 -13.241,10.03 36.423,10.047 68.337,10.061 -75.438,10.111 61.712,10.207 65.787,10.229 -50.218,10.286 -25.513,10.283 32.113,10.29 38.355,10.275 2.487,10.316 -15.043,10.386 67.313,10.415 -27.479,10.475 16.165,10.527 48.028,10.563 -73.912,10.587 30.587,10.604 13.941,10.654 53.988,10.691 -36.172,10.732 -29.72,10.726 69.863,10.744 -31.84,10.764 -17.516,10.763 -54.524,10.792 -42.479,10.792 72.463,10.804 -21.262,10.959 17.137,11.009 18.887,11.009 -53.075,11.075 -23.305,11.074 0.353,11.075 9.781,11.062 11.881,11.062 -44.348,11.081 -18.991,11.113 -11.441,11.112 -9.341,11.112 -7.241,11.112 -5.141,11.112 -3.041,11.112 -39.685,11.294 4.013,11.318 -46.952,11.393 -33.268,11.478 52.763,11.516 55.213,11.516 34.963,11.556 63.22,11.567 7.766,11.654 50.538,11.719 36.87,11.76 -48.733,11.771 -24.028,11.768 -13.558,11.871 -25.994,11.96 21.976,11.962 -16.691,11.988 45.412,12.013 70.937,11.994 14.712,12.043 -55.32,12.082 60.781,12.089 68.337,12.161 -75.438,12.211 -34.687,12.217 -28.235,12.211 -30.355,12.249 -40.994,12.277 65.787,12.329 46.938,12.358 32.113,12.39 2.487,12.416 49.012,12.419 16.787,12.484 19.237,12.484 -52.792,12.524 -36.311,12.51 67.313,12.515 40.518,12.533 -42.863,12.566 -21.816,12.555 -1.104,12.587 10.584,12.588 12.684,12.588 -11.604,12.638 -9.504,12.638 -7.404,12.638 -5.304,12.638 -3.204,12.638 19.993,12.652 -73.912,12.687 30.587,12.704 -38.2,12.779 -19.727,12.763 23.895,12.816 69.863,12.844 -45.467,12.878 -18.991,12.863 42.588,12.884 72.463,12.904 -31.783,12.963 53.113,12.991 54.863,12.991 8.534,13.045 6.302,13.16 61.861,13.168 -17.516,13.213 -47.248,13.256 -22.543,13.253 18.012,13.309 -54.082,13.32 4.013,13.418 -24.509,13.445 59.296,13.574 34.837,13.652 -33.202,13.702 -26.75,13.696 -28.87,13.734 21.07,13.735 -39.509,13.762 -56.863,13.784 36.363,13.798 50.538,13.819 -20.525,13.837 -18.425,13.837 -16.325,13.837 -14.225,13.837 -12.125,13.837 -10.025,13.837 -7.925,13.837 -5.825,13.837 38.925,13.901 14.152,13.962 16.252,13.962 18.352,13.962 -34.826,13.995 -3.734,14.028 -41.378,14.051 40.91,14.07 70.94,14.094 45.412,14.113 23.118,14.198 -74.991,14.263 -36.715,14.264 68.337,14.261 -43.983,14.363 -72.696,14.399 65.787,14.429 -30.298,14.448 46.938,14.458 32.113,14.49 2.487,14.516 49.012,14.519 67.313,14.615 60.376,14.653 43.663,14.688 24.763,14.728 -45.764,14.741 73.458,14.754 30.587,14.804 12.232,14.814 -55.803,14.883 -23.024,14.93 69.863,14.944 7.688,14.968 57.812,15.059 -31.717,15.187 -25.265,15.18 -27.385,15.219 53.237,15.215 19.585,15.22 -58.348,15.269 6.162,15.255 -20.969,15.363 -18.869,15.363 -16.769,15.363 -14.669,15.363 -12.569,15.363 -10.469,15.363 -8.369,15.363 -6.269,15.363 -33.341,15.48 15.402,15.488 17.502,15.488 -2.241,15.504 4.013,15.518 -70.931,15.537 -68.831,15.537 -66.731,15.537 -64.631,15.537 -62.531,15.537 -60.431,15.537 -39.893,15.536 54.763,15.54 -4.198,15.707 72.267,15.722 -73.506,15.748 -35.23,15.749 34.837,15.752 42.137,15.774 -42.498,15.848 36.363,15.898 50.538,15.919 -28.813,15.933 38.712,15.99 40.238,16.059 58.892,16.138 -44.279,16.226 45.412,16.213 23.237,16.294 68.337,16.361 -57.288,16.368 65.787,16.529 46.938,16.558 31.913,16.58 56.353,16.57 2.487,16.616 49.012,16.619 -23.78,16.665 -48.012,16.691 -30.232,16.672 29.658,16.687 59.988,16.691 -25.9,16.704 67.313,16.715 74.264,16.693 -36.539,16.732 -11.516,16.763 43.663,16.788 11.687,16.841 -31.856,16.965 -0.756,16.989 8.285,16.981 -38.409,17.021 13.957,17.012 16.057,17.012 18.157,17.012 20.257,17.012 23.137,17.009 24.887,17.009 69.863,17.044 -71.869,17.063 -69.769,17.063 -67.669,17.063 -65.569,17.063 -63.469,17.063 -61.369,17.063 -59.269,17.063 -12.991,17.113 -2.713,17.192 -33.745,17.234 -21.759,17.237 -19.659,17.237 -17.559,17.237 -15.459,17.237 53.237,17.315 6.477,17.331 -27.328,17.417 33.583,17.437 -49.237,17.516 -46.787,17.516 58.763,17.516 61.213,17.516 4.41,17.581 54.763,17.64 -41.612,17.752 35.41,17.769 42.137,17.874 57.763,17.909 -43.138,17.989 -10.691,17.988 38.116,18.004 50.538,18.019 30.434,18.071 -28.747,18.157 40.089,18.154 -24.416,18.189 28.173,18.172 -35.054,18.216 45.127,18.294 21.841,18.39 -30.371,18.45 9.77,18.466 13.013,18.47 68.337,18.461 0.729,18.474 22.787,18.484 25.237,18.484 -36.924,18.506 15.112,18.538 17.212,18.538 19.312,18.538 3.245,18.574 65.445,18.601 46.851,18.657 56.237,18.667 -32.261,18.719 49.012,18.719 -22.396,18.763 -20.296,18.763 -18.196,18.763 -16.096,18.763 -13.996,18.763 74.264,18.793 7.962,18.816 67.265,18.814 -12.991,18.863 -25.843,18.902 32.098,18.922 -48.887,18.991 -47.137,18.991 59.113,18.991 60.863,18.991 5.895,19.065 69.863,19.144 52.284,19.187 -11.516,19.213 24.012,19.309 36.631,19.489 28.949,19.556 -23.858,19.587 -21.758,19.587 -19.658,19.587 -17.558,19.587 -15.458,19.587 -13.358,19.587 -9.158,19.587 -7.058,19.587 -4.958,19.587 -2.858,19.587 -27.263,19.642 26.688,19.657 38.622,19.657 54.174,19.656 -33.569,19.701 43.172,19.701 11.361,19.837 13.461,19.837 15.561,19.837 17.661,19.837 -41.612,19.852 -28.886,19.935 2.214,19.959 -35.439,19.991 45.248,20.013 57.763,20.009 4.73,20.059 -43.138,20.089 63.97,20.096 0.257,20.162 -30.776,20.204 -48.763,20.297 9.447,20.301 65.844,20.361 50.285,20.389 30.613,20.407 -0.936,20.434 21.559,20.471 67.688,20.458 7.38,20.55 55.621,20.675 52.359,20.713 32.441,20.739 -47.237,20.955 27.464,21.041 -25.717,21.064 -23.617,21.113 -21.517,21.113 -19.417,21.113 -17.317,21.113 -15.217,21.113 -13.117,21.113 -11.017,21.113 -8.917,21.113 -6.817,21.113 -4.717,21.113 -2.617,21.113 35.312,21.123 69.176,21.128 25.203,21.142 -32.084,21.186 59.237,21.215 11.258,21.363 13.358,21.363 15.458,21.363 17.558,21.363 19.658,21.363 -27.401,21.42 -33.954,21.476 60.763,21.538 -40.398,21.565 6.215,21.544 3.513,21.609 -29.291,21.689 -25.333,21.787 -23.233,21.787 -21.133,21.787 -19.033,21.787 -16.933,21.787 -14.833,21.787 -12.733,21.787 -10.633,21.787 -8.533,21.787 -6.433,21.787 56.659,21.795 -4.333,21.8 29.129,21.892 0.549,21.919 -42.17,21.953 8.865,22.035 66.313,22.045 54.136,22.16 63.787,22.188 30.956,22.224 -48.92,22.391 65.313,22.393 10.931,22.412 13.031,22.412 15.131,22.412 17.231,22.412 19.331,22.412 21.431,22.412 23.531,22.412 25.979,22.525 -30.599,22.671 67.813,22.726 -32.469,22.961 7.7,23.029 -47.431,23.046 -38.913,23.05 -27.789,23.157 -2.723,23.148 37.713,23.162 39.813,23.162 41.913,23.162 44.013,23.162 46.113,23.162 35.438,23.219 55.174,23.28 -25.695,23.313 -23.595,23.313 -21.495,23.313 -19.395,23.313 -17.295,23.313 -15.195,23.313 -13.095,23.313 -10.995,23.313 -8.895,23.313 -6.795,23.313 59.237,23.315 74.745,23.303 -4.695,23.334 27.644,23.377 -40.685,23.437 48.188,23.484 60.763,23.638 52.703,23.694 3.513,23.709 29.471,23.709 1.987,23.732 71.975,23.816 -50.405,23.876 -28.887,23.887 -26.787,23.887 -24.687,23.887 -22.587,23.887 -20.487,23.887 -18.387,23.887 -16.287,23.887 -14.187,23.887 -12.087,23.887 -9.987,23.887 -7.887,23.887 -5.787,23.887 -71.405,23.912 -69.305,23.912 -67.205,23.912 -65.105,23.912 -63.005,23.912 -60.905,23.912 -58.805,23.912 -56.705,23.912 -54.605,23.912 -52.505,23.912 24.399,23.909 9.593,23.938 11.693,23.938 13.793,23.938 15.893,23.938 17.993,23.938 20.093,23.938 22.193,23.938 66.287,24.145 70.476,24.214 76.566,24.234 0.073,24.278 63.787,24.288 -30.984,24.446 65.313,24.493 -48.908,24.538 -37.428,24.535 -1.238,24.633 -73.366,24.662 39.076,24.688 41.176,24.688 43.276,24.688 45.376,24.688 -3.21,24.819 67.813,24.826 26.159,24.862 9.359,24.889 11.459,24.889 13.559,24.889 15.659,24.889 17.759,24.889 19.859,24.889 21.959,24.889 24.059,24.889 7.259,24.921 47.463,24.918 -39.2,24.922 -4.049,25.065 54.163,25.121 27.986,25.194 49.413,25.189 74.348,25.365 -29.12,25.413 -27.02,25.413 -24.92,25.413 -22.82,25.413 -20.72,25.413 -18.62,25.413 -16.52,25.413 -14.42,25.413 -12.32,25.413 -10.22,25.413 -8.12,25.413 -6.02,25.413 59.237,25.415 -71.805,25.438 -69.705,25.438 -67.605,25.438 -65.505,25.438 -63.405,25.438 -61.305,25.438 -59.205,25.438 -57.105,25.438 -55.005,25.438 -52.905,25.438 -50.805,25.438 60.763,25.738 3.513,25.809 52.637,25.793 1.987,25.832 72.576,25.828 -35.943,26.02 -33.843,26.062 -31.743,26.062 -29.643,26.062 -27.543,26.062 -25.443,26.062 -23.343,26.062 -21.243,26.062 -19.143,26.062 -17.043,26.062 -14.943,26.062 -12.843,26.062 -10.743,26.062 -8.643,26.062 -6.543,26.062 -74.851,26.147 75.717,26.155 71.05,26.234 66.287,26.245 -1.725,26.304 5.683,26.309 0.073,26.378 63.787,26.388 9.478,26.416 11.578,26.416 13.678,26.416 15.778,26.416 17.878,26.416 19.978,26.416 22.078,26.416 24.178,26.416 26.278,26.416 -2.564,26.55 65.313,26.593 55.505,26.737 57.605,26.737 -4.457,26.816 -73.377,26.831 72.887,26.874 67.813,26.926 47.718,27.002 7.836,27.277 9.936,27.277 12.036,27.277 14.136,27.277 16.236,27.277 18.336,27.277 20.436,27.277 22.536,27.277 24.636,27.277 26.736,27.277 28.836,27.277 30.936,27.277 33.036,27.277 35.136,27.277 37.236,27.277 39.336,27.277 41.436,27.277 43.536,27.277 45.636,27.277 49.386,27.289 53.807,27.537 -35.978,27.588 -33.878,27.588 -31.778,27.588 -29.678,27.588 -27.578,27.588 -25.478,27.588 -23.378,27.588 -21.278,27.588 -19.178,27.588 -17.078,27.588 -14.978,27.588 -12.878,27.588 -10.778,27.588 -8.678,27.588 -6.578,27.588 59.885,27.645 74.288,27.694 4.198,27.794 -76.113,27.825 72.576,27.928 55.778,28.263 57.878,28.263 6.011,28.317 66.287,28.345 71.05,28.334 0.023,28.478 63.787,28.488 -74.587,28.548 65.313,28.693 47.902,28.776 8.003,28.804 10.103,28.804 12.203,28.804 14.303,28.804 16.403,28.804 18.503,28.804 20.603,28.804 22.703,28.804 24.803,28.804 26.903,28.804 29.003,28.804 31.103,28.804 33.203,28.804 35.303,28.804 39.503,28.804 41.603,28.804 43.703,28.804 45.803,28.804 72.761,28.97 67.813,29.026 -17.116,29.161 -59.116,29.187 -57.016,29.187 -54.916,29.187 -52.816,29.187 -50.716,29.187 -48.616,29.187 -46.516,29.187 -44.416,29.187 -42.316,29.187 -40.216,29.187 -38.116,29.187 -36.016,29.187 -31.816,29.187 -29.716,29.187 -27.616,29.187 -25.516,29.187 -23.416,29.187 -21.316,29.187 -19.216,29.187 -61.207,29.372 8.486,29.527 10.586,29.527 12.686,29.527 14.786,29.527 16.886,29.527 18.986,29.527 -14.074,29.638 -11.974,29.638 -9.874,29.638 -7.774,29.638 21.081,29.678 4.541,29.816 -76.113,29.925 71.968,29.938 53.769,29.987 55.869,29.987 57.969,29.987 60.069,29.995 -16.074,30.279 -14.254,30.295 66.287,30.445 63.787,30.588 -74.587,30.648 -60.129,30.713 -58.029,30.713 -55.929,30.713 -53.829,30.713 -51.729,30.713 -49.629,30.713 -47.529,30.713 -45.429,30.713 -43.329,30.713 -41.229,30.713 -39.129,30.713 -34.929,30.713 -32.829,30.713 -30.729,30.713 -28.629,30.713 -26.529,30.713 -24.429,30.713 -22.329,30.713 -20.229,30.713 -18.129,30.713 65.313,30.793 -62.702,30.847 18.165,31.054 20.265,31.054 51.962,31.058 22.584,31.145 67.813,31.126 24.677,31.312 26.777,31.312 28.877,31.312 30.977,31.312 33.077,31.312 35.177,31.312 37.277,31.312 39.377,31.312 41.477,31.312 43.577,31.312 61.687,31.333 9.847,31.402 11.947,31.402 14.047,31.402 16.147,31.402 55.14,31.513 57.24,31.513 59.34,31.513 -11.675,31.69 -9.575,31.69 7.769,31.705 -15.761,31.757 -13.763,31.917 -76.113,32.025 -61.747,32.052 53.114,32.066 45.511,32.131 -64.187,32.332 17.998,32.394 -32.439,32.462 -30.339,32.462 -28.239,32.462 -26.139,32.462 -24.039,32.462 -21.939,32.462 -19.839,32.462 -17.739,32.462 21.784,32.504 66.287,32.545 63.787,32.688 -74.587,32.748 60.998,32.802 23.857,32.838 25.957,32.838 28.057,32.838 30.157,32.838 32.257,32.838 34.357,32.838 36.457,32.838 38.557,32.838 40.657,32.838 42.757,32.838 65.313,32.893 12.411,32.929 14.511,32.929 51.162,32.999 10.356,33.152 16.599,33.153 62.713,33.165 67.813,33.226 75.825,33.224 -15.248,33.402 -13.233,33.399 8.279,33.46 -10.159,33.509 44.743,33.522 -63.232,33.537 46.995,33.616 12.388,33.684 -34.133,33.703 -65.672,33.817 19.483,33.879 -31.964,33.988 -29.864,33.988 -27.764,33.988 -25.664,33.988 -23.564,33.988 -21.464,33.988 -17.264,33.988 -75.575,34.055 -73.171,34.299 -12.065,34.39 -9.834,34.631 18.084,34.638 9.703,34.718 77.286,34.733 63.787,34.788 65.313,34.993 -64.717,35.021 46.228,35.007 50.579,35.017 48.48,35.101 7.649,35.154 13.873,35.169 -35.618,35.188 11.747,35.201 -7.355,35.228 62.713,35.265 -67.157,35.302 -33.589,35.319 -29.373,35.312 -27.273,35.312 -25.173,35.312 -23.073,35.312 -20.973,35.312 -18.873,35.312 -16.773,35.312 -71.356,35.355 -69.256,35.355 20.968,35.364 23.068,35.412 25.168,35.412 27.268,35.412 29.368,35.412 31.468,35.412 33.568,35.412 35.668,35.412 37.768,35.412 39.868,35.412 41.968,35.412 -56.596,35.487 -54.496,35.487 -52.396,35.487 -50.296,35.487 -48.196,35.487 -46.096,35.487 -43.996,35.487 -41.896,35.487 -39.796,35.487 -74.09,35.54 -13.55,35.875 -58.655,35.901 51.752,36.002 -11.319,36.116 19.569,36.123 43.946,36.116 75.887,36.121 5.809,36.168 67.797,36.164 -9.226,36.181 -31.154,36.425 47.713,36.492 -66.202,36.506 49.795,36.763 77.413,36.829 -28.016,36.838 -25.916,36.838 -23.816,36.838 -21.716,36.838 -19.616,36.838 -17.516,36.838 -15.416,36.838 -72.468,36.874 -70.368,36.881 -68.268,36.881 63.787,36.888 21.504,36.938 23.604,36.938 25.704,36.938 27.804,36.938 29.904,36.938 32.004,36.938 34.104,36.938 36.204,36.938 38.304,36.938 40.404,36.938 42.504,36.938 61.187,36.994 -56.066,37.013 -53.966,37.013 -51.866,37.013 -49.766,37.013 -47.666,37.013 -45.566,37.013 -43.466,37.013 -39.266,37.013 12.662,37.091 65.313,37.093 71.207,37.137 -5.851,37.198 -8.029,37.217 14.188,37.245 -60.14,37.386 -30.024,37.454 -58.106,37.511 45.431,37.601 -10.711,37.666 -12.363,37.938 5.337,37.936 6.863,37.984 68.825,37.995 10.841,38.137 75.887,38.221 47.416,38.287 49.516,38.287 51.616,38.287 53.716,38.287 55.816,38.287 44.04,38.37 -4.163,38.49 57.9,38.545 -61.625,38.871 -31.509,38.938 77.413,38.929 28.499,38.962 63.787,38.988 -59.591,38.996 30.597,39.034 -6.837,39.052 13.156,39.073 61.187,39.094 9.008,39.162 65.313,39.193 -8.363,39.29 4.025,39.309 62.713,39.465 11.14,39.663 -10.837,39.762 45.602,39.774 47.702,39.813 49.802,39.813 51.902,39.813 54.002,39.813 56.102,39.813 -12.363,40.038 5.337,40.036 6.863,40.084 26.719,40.077 68.804,40.095 -27.763,40.112 -25.663,40.112 -23.563,40.112 -21.463,40.154 59.188,40.203 75.887,40.321 -63.11,40.356 -1.639,40.39 -32.994,40.423 -61.076,40.481 32.127,40.473 -4.259,40.553 30.075,40.579 66.789,40.687 73.359,40.719 -35.609,40.879 -5.859,40.911 28.007,40.947 34.157,41.012 36.257,41.012 38.357,41.012 40.457,41.012 42.557,41.012 77.413,41.029 64.087,41.066 -29.603,41.124 8.462,41.19 61.187,41.194 57.662,41.219 -7.661,41.269 10.081,41.476 -19.907,41.564 62.713,41.565 75.254,41.624 -26.3,41.638 -24.2,41.638 -22.1,41.638 25.34,41.66 -64.595,41.84 -10.837,41.862 -0.838,41.844 -34.479,41.908 -62.561,41.966 12.111,42.012 14.211,42.012 16.311,42.012 18.411,42.012 -28.361,42.041 31.56,42.064 44.381,42.052 -12.363,42.138 5.337,42.136 6.863,42.184 65.846,42.213 72.565,42.216 20.5,42.226 51.653,42.287 53.753,42.287 55.853,42.287 59.059,42.299 -37.094,42.364 4.069,42.408 75.887,42.421 33.606,42.538 35.706,42.538 37.806,42.538 39.906,42.538 42.006,42.538 68.395,42.568 -31.088,42.609 26.838,42.692 -4.912,42.785 -6.438,42.976 65,43 9.475,43.029 -18.422,43.048 -20.562,43.068 77.413,43.129 73.949,43.269 61.187,43.294 -66.08,43.325 -35.964,43.393 0.688,43.429 -64.046,43.45 -29.846,43.526 11.512,43.538 13.612,43.538 15.712,43.538 17.812,43.538 49.974,43.547 62.713,43.665 21.988,43.708 25.312,43.76 57.543,43.753 19.899,43.778 53.344,43.813 55.444,43.813 66.875,43.8 -38.579,43.849 43.587,43.92 -0.838,43.944 -10.837,43.962 45.113,44.02 -32.573,44.094 -12.363,44.238 5.337,44.236 6.863,44.284 51.317,44.363 75.887,44.521 -19.077,44.553 -17.237,44.782 -67.565,44.81 26.838,44.792 -37.449,44.878 -4.912,44.885 -65.531,44.935 -31.331,45.011 65,45 48.489,45.032 -6.438,45.076 77.413,45.229 -40.064,45.334 21.287,45.354 61.187,45.394 4.069,45.508 0.688,45.529 -34.058,45.578 31.821,45.596 33.921,45.596 36.021,45.596 38.121,45.596 40.221,45.596 42.321,45.596 22.813,45.639 62.713,45.765 49.832,45.848 25.312,45.86 44.407,45.998 -0.838,46.044 -10.837,46.062 -12.363,46.338 5.337,46.336 -38.934,46.363 6.863,46.384 29.866,46.364 -68.904,46.428 -67.016,46.42 -32.816,46.496 47.049,46.561 -54.012,46.691 18.484,46.763 53.476,46.792 -41.549,46.819 26.838,46.892 -4.912,46.985 -18.863,47.009 -17.113,47.009 65,47 -35.543,47.063 54.925,47.075 17.009,47.113 32.134,47.123 36.334,47.123 38.434,47.123 40.534,47.123 42.634,47.123 -6.438,47.176 14.03,47.237 16.13,47.237 60.166,47.229 11.931,47.308 77.413,47.329 21.287,47.454 48.501,47.472 -55.237,47.516 -52.787,47.516 0.688,47.629 61.867,47.687 22.94,47.735 -40.362,47.903 25.03,47.941 -34.301,47.981 19.309,47.988 52.68,48.082 -11.158,48.138 -0.838,48.144 -13.364,48.184 28.862,48.208 30.388,48.291 5.337,48.436 -67.387,48.487 -19.213,48.484 -16.763,48.484 6.863,48.484 -68.913,48.528 55.208,48.524 4.069,48.608 46.974,48.659 58.682,48.714 10.4,48.746 13.372,48.763 15.472,48.763 -36.688,48.823 52.117,48.803 17.009,48.863 -41.888,48.891 26.228,48.901 -54.887,48.991 -53.137,48.991 65,49 -4.912,49.085 60.382,49.172 18.484,49.213 -6.438,49.276 22.325,49.279 -17.988,49.309 53.918,49.32 77.413,49.429 48.501,49.572 -12.643,49.623 -14.849,49.669 0.688,49.729 11.531,49.774 24.349,49.838 31.809,49.837 33.909,49.837 36.009,49.837 -53.237,49.861 38.109,49.844 -35.162,49.896 -40.362,50.003 -25.277,50.212 -23.177,50.212 -21.077,50.212 -18.977,50.212 -16.877,50.212 57.197,50.199 -27.377,50.227 -0.838,50.244 29.326,50.256 52.888,50.489 5.337,50.536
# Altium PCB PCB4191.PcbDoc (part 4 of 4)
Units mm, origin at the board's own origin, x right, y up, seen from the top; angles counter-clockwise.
Board outline 160 x 160 mm, 6 copper layers (Top Layer, IM1 RIS, IM2 Signal, IM3 Signal, IM4 GND, Bottom Layer), stack 1.582 mm thick; 143 components, 121 nets, 430 pads, 4960 vias.

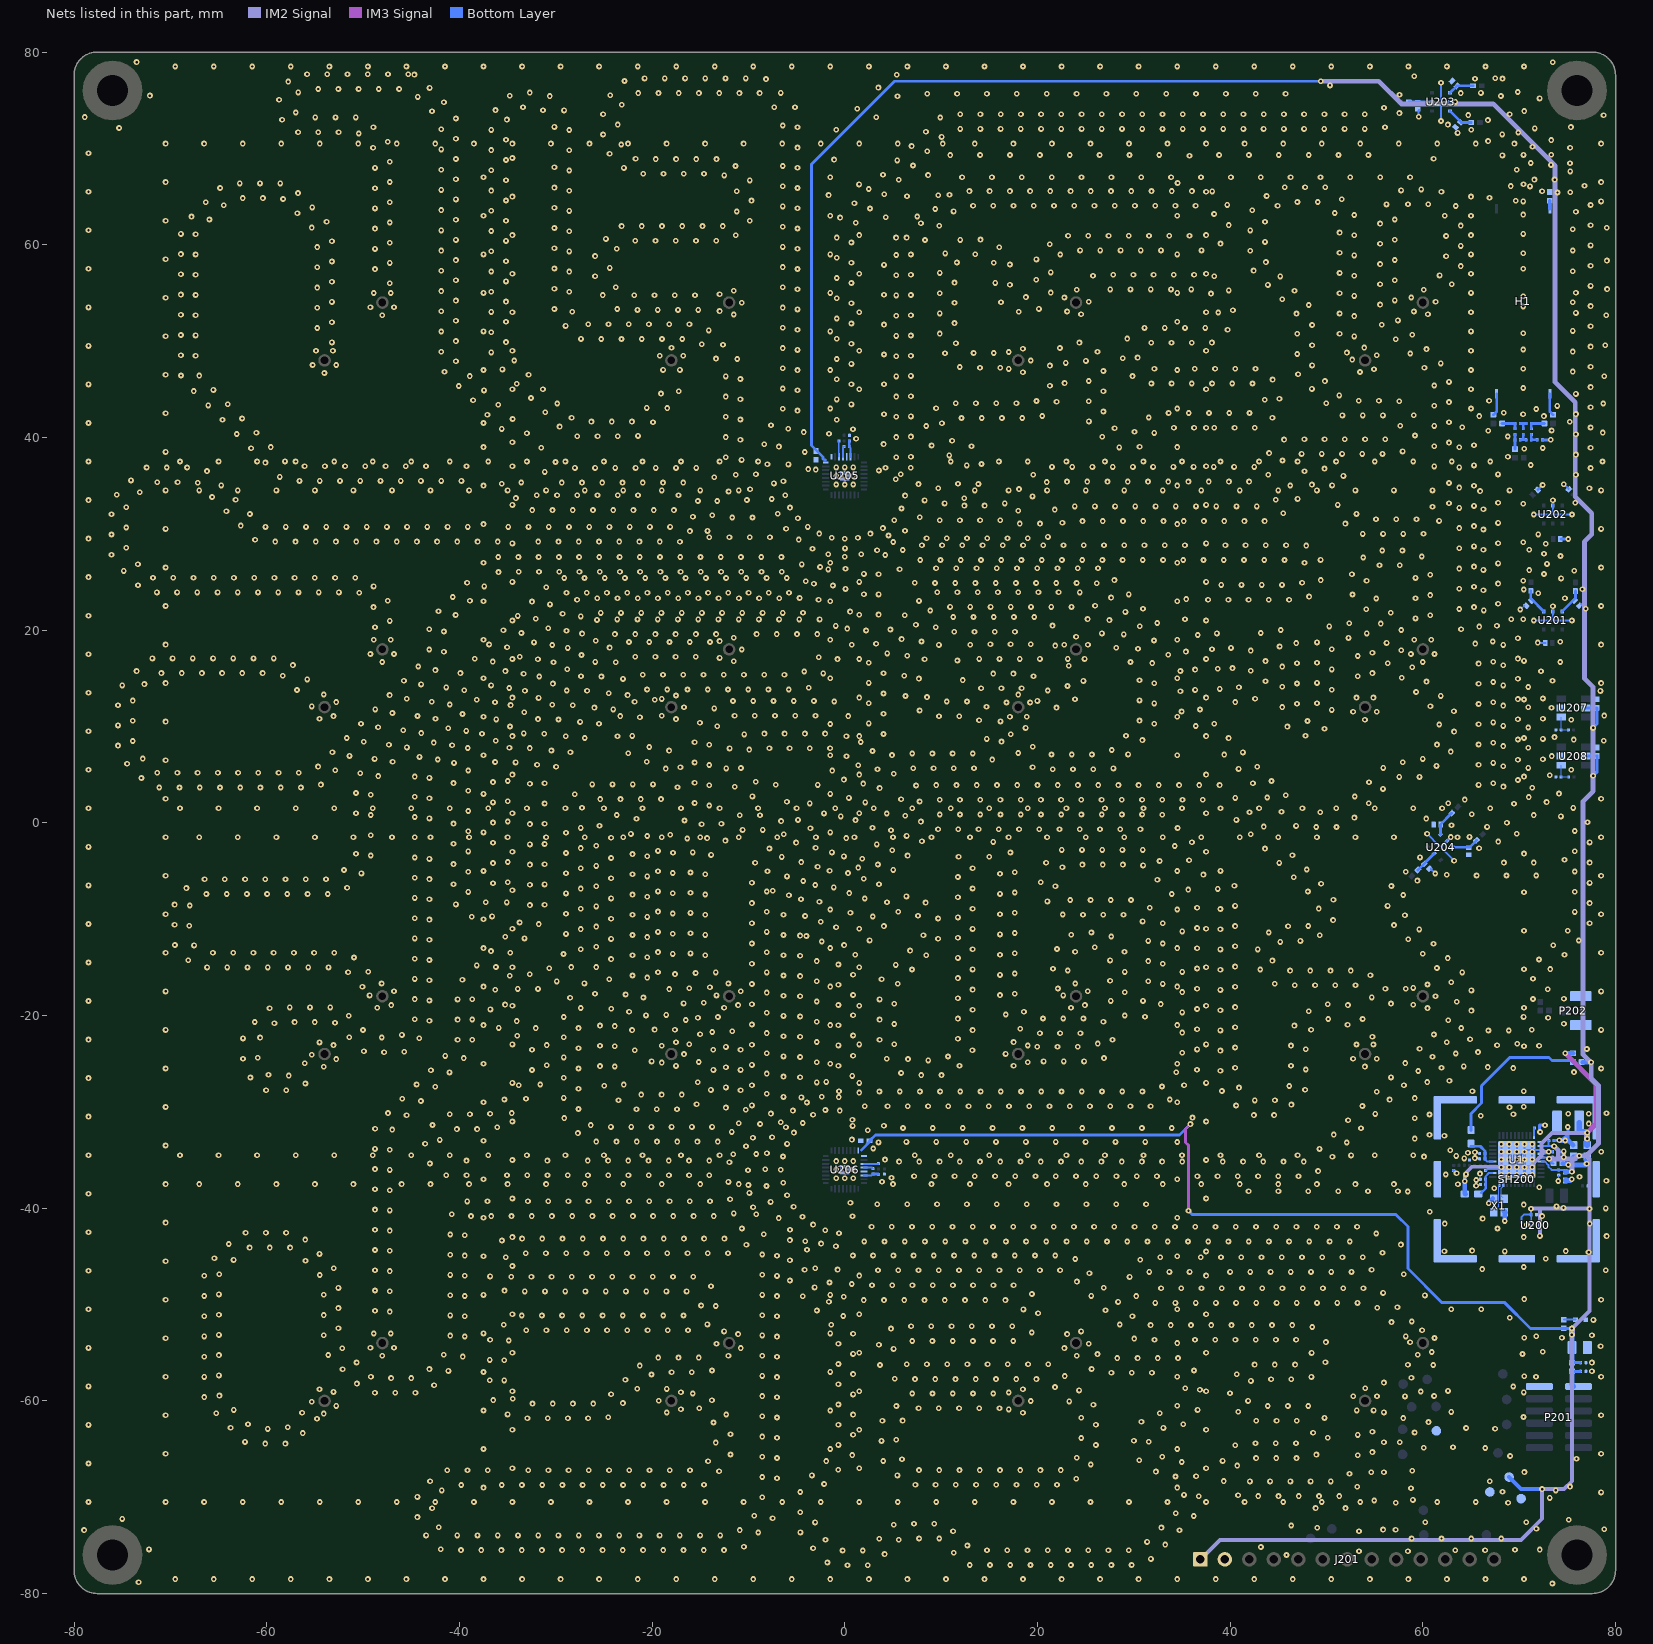
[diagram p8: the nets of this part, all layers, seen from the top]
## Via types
v1: diameter 0.6, hole 0.25, IM4 GND to Bottom Layer, tented bottom, 3930 vias
v2: diameter 0.6, hole 0.25, Top Layer to Bottom Layer, tented both sides, 851 vias
v3: diameter 0.6, hole 0.25, IM4 GND to Bottom Layer, tented both sides, 179 vias

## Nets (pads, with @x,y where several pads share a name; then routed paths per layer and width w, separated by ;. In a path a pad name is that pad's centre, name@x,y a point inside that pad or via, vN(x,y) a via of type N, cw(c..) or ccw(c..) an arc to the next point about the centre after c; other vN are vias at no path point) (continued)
GND: (continued)
  other v1: -67.387,50.587 6.863,50.584 -68.913,50.628 58.897,50.657 9.862,50.775 46.974,50.759 51.362,50.762 -36.688,50.923 -41.888,50.991 65,51 -14.128,51.108 -4.912,51.185 39.732,51.177 -54.763,51.353 31.11,51.363 33.21,51.363 35.31,51.363 37.41,51.363 -6.438,51.376 77.413,51.529 -28.984,51.579 48.501,51.672 4.069,51.708 55.726,51.698 -26.631,51.738 -24.531,51.738 -22.431,51.738 -20.331,51.738 -18.231,51.738 -16.131,51.738 0.688,51.829 11.388,51.869 -53.237,51.961 -35.162,51.996 -40.362,52.103 57.412,52.142 -0.838,52.344 52.888,52.589 5.337,52.636 6.863,52.684 -67.387,52.687 -48.012,52.691 -68.913,52.728 -11.516,52.763 24.524,52.792 60.524,52.792 46.888,52.857 9.862,52.875 51.362,52.862 75.887,52.921 38.762,52.971 65,53 -36.688,53.023 -28.282,53.036 18.066,53.037 23.075,53.075 59.075,53.075 -41.888,53.091 -12.991,53.113 40.288,53.202 -21.515,53.237 -19.415,53.237 -17.315,53.237 -15.215,53.237 -4.912,53.285 -30.138,53.334 -23.613,53.326 20.144,53.339 -54.763,53.453 -6.438,53.476 -49.237,53.516 -46.787,53.516 77.413,53.629 48.16,53.744 55.562,53.792 0.688,53.929 11.388,53.969 -10.691,53.988 16.215,54.03 -53.237,54.061 -35.162,54.096 25.32,54.082 61.32,54.082 -40.362,54.203 57.088,54.217 45.403,54.342 -0.838,54.444 22.792,54.524 58.792,54.524 18.797,54.563 52.888,54.689 5.337,54.736 -21.85,54.763 -19.75,54.763 -17.65,54.763 -15.55,54.763 -67.387,54.787 -25.132,54.777 6.863,54.784 4.069,54.808 -68.913,54.828 -12.991,54.863 38.013,54.933 51.362,54.962 -48.887,54.991 -47.137,54.991 9.862,54.975 65,55 21.388,55.031 75.887,55.021 -28.612,55.11 -36.688,55.123 -41.888,55.191 -11.516,55.213 46.675,55.229 39.849,55.256 24.082,55.32 60.082,55.32 27.557,55.362 29.657,55.362 31.757,55.362 33.857,55.362 35.957,55.362 -4.912,55.385 -30.138,55.434 -54.763,55.553 -6.438,55.576 -23.782,55.587 77.413,55.729 43.918,55.827 17.138,55.852 55.562,55.892 62.989,55.91 -47.237,56.01 0.688,56.029 15.612,56.041 11.388,56.069 -53.237,56.161 -35.162,56.196 -40.362,56.303 57.088,56.317 19.862,56.373 -0.838,56.544 45.19,56.714 -25.913,56.726 38.349,56.725 25.758,56.78 52.888,56.789 61.737,56.817 5.337,56.836 -67.387,56.887 6.863,56.884 27.855,56.888 29.955,56.888 32.055,56.888 34.155,56.888 36.255,56.888 -68.913,56.928 65,57 9.862,57.075 51.362,57.062 21.388,57.131 -36.688,57.223 -28.612,57.21 -41.888,57.291 42.433,57.312 -48.763,57.471 -4.912,57.485 -30.138,57.534 -24.387,57.598 -54.763,57.653 -6.438,57.676 63.938,57.783 77.413,57.829 4.069,57.908 17.138,57.952 55.562,57.992 -47.237,58.11 0.688,58.129 15.46,58.136 11.634,58.154 43.706,58.199 -53.237,58.261 -35.162,58.296 -40.362,58.403 57.088,58.417 19.891,58.473 -0.838,58.644 62.412,58.805 -25.913,58.826 52.888,58.889 5.337,58.936 -67.387,58.987 6.863,58.984 22.368,58.988 65,59 -68.913,59.028 13.551,59.012 10.42,59.1 51.362,59.162 -28.612,59.31 -36.688,59.323 42.087,59.383 -41.888,59.391 24.425,59.412 26.525,59.412 28.625,59.412 30.725,59.412 32.825,59.412 37.025,59.412 -48.763,59.571 -23.673,59.573 -4.912,59.585 -30.138,59.634 16.023,59.731 -54.763,59.753 -6.438,59.776 63.938,59.883 77.413,59.929 21.274,60.053 55.562,60.092 39.001,60.122 -47.237,60.21 0.688,60.229 43.613,60.297 -53.237,60.361 -35.162,60.396 -21.748,60.412 -19.648,60.412 -17.548,60.412 -15.448,60.412 -13.348,60.412 -40.362,60.503 8.323,60.494 11.985,60.5 57.088,60.517 14.085,60.538 -24.799,60.606 -0.838,60.744 5.324,60.743 6.411,60.741 62.412,60.905 23.178,60.938 25.278,60.938 27.378,60.938 29.478,60.938 31.578,60.938 33.678,60.938 35.778,60.938 52.888,60.989 -11.329,60.991 65,61 -67.387,61.087 -68.913,61.128 51.362,61.262 -28.612,61.41 -36.688,61.423 -41.888,61.491 42.087,61.483 -48.763,61.671 -4.912,61.685 -30.138,61.734 -55.33,61.775 -6.438,61.876 -23.172,61.934 -21.072,61.938 -18.972,61.938 -16.872,61.938 -14.772,61.938 -12.672,61.938 9.808,61.978 63.938,61.983 77.413,62.029 39.863,62.036 55.562,62.192 7.896,62.226 1.135,62.281 -47.237,62.31 -53.784,62.389 43.613,62.397 -35.162,62.496 -9.857,62.489 -40.362,62.603 -65.951,62.62 57.088,62.617 -0.49,62.815 4.262,62.846 -67.813,62.917 7.516,62.935 62.27,63 65,63 52.888,63.089 38.337,63.194 -56.815,63.26 50.847,63.298 75.887,63.421 -11.213,63.449 11.293,63.463 -36.688,63.523 -28.612,63.51 42.299,63.573 -41.888,63.591 9.381,63.71 -48.763,63.771 2.62,63.766 -4.912,63.785 -30.138,63.834 -55.269,63.873 -6.438,63.976 13.313,64.037 15.413,64.037 17.513,64.037 19.613,64.037 21.713,64.037 23.813,64.037 25.913,64.037 28.013,64.037 30.113,64.037 32.213,64.037 34.313,64.037 36.413,64.037 63.413,64.017 44.92,64.041 -64.466,64.105 39.697,64.13 77.413,64.129 56.229,64.183 58.455,64.212 60.555,64.212 0.995,64.3 -66.328,64.401 -47.237,64.41 46.982,64.437 49.082,64.437 69.651,64.562 -35.162,64.596 -9.687,64.582 -40.362,64.703 -58.3,64.745 51.576,64.729 -62.498,64.837 -60.398,64.837 66.916,64.878 65,65 6.454,65.038 43.781,65.06 9.708,65.127 -1.677,65.149 10.866,65.195 4.105,65.251 -56.754,65.358 75.306,65.44 61.928,65.501 38.133,65.532 -11.213,65.549 12.933,65.563 15.033,65.563 17.133,65.563 19.233,65.563 21.333,65.563 23.433,65.563 25.533,65.563 27.633,65.563 29.733,65.563 31.833,65.563 33.933,65.563 36.033,65.563 -28.612,65.61 -36.688,65.623 57.744,65.637 -41.888,65.691 59.841,65.738 2.48,65.785 -64.843,65.886 -48.763,65.871 -4.912,65.885 -30.138,65.934 45.677,65.963 47.777,65.963 49.877,65.963 71.124,66.059 -6.438,66.076 76.775,66.129 -62.798,66.363 -60.698,66.363 -58.598,66.363 -47.237,66.51 -9.867,66.675 -35.162,66.696 5.59,66.736 71.575,66.762 73.675,66.762 -40.362,66.803 12.173,67.006 15.273,67.006 18.373,67.006 21.473,67.006 24.573,67.006 27.673,67.006 30.773,67.006 33.873,67.006 36.973,67.006 40.073,67.006 43.173,67.006 46.273,67.006 49.373,67.006 52.473,67.006 55.573,67.006 58.673,67.006 -12.521,67.192 8.646,67.23 3.965,67.27 -20.915,67.362 -18.815,67.362 -16.715,67.362 -14.615,67.362 75.29,67.614 -28.612,67.71 -36.688,67.723 -41.888,67.791 69.743,67.789 -48.763,67.971 -22.925,67.97 -4.912,67.985 -30.138,68.034 -11.341,68.17 -6.438,68.176 7.075,68.22 73.301,68.288 71.21,68.481 -47.237,68.61 5.45,68.754 -35.162,68.796 -1.11,68.839 -19.614,68.888 -17.514,68.888 -15.414,68.888 -13.314,68.888 -40.362,68.903 -21.714,68.918 61.113,68.919 68.258,69.274 10.948,69.306 14.048,69.319 17.148,69.319 20.248,69.319 23.348,69.319 26.448,69.319 29.548,69.319 32.648,69.319 38.848,69.319 41.948,69.319 45.048,69.319 48.148,69.319 51.248,69.319 54.348,69.319 73.317,69.337 -24.409,69.455 8.56,69.705 -36.688,69.823 -28.612,69.81 -41.888,69.891 -48.966,70.061 75.283,70.074 -4.912,70.085 71.385,70.161 6.935,70.239 -23.199,70.403 -47.45,70.699 66.773,70.759 73.337,70.863 -35.162,70.896 -40.362,71.003 10.045,71.19 -25.088,71.442 68.24,71.451 -50.451,71.546 69.9,71.646 -56.746,71.687 -54.646,71.687 -52.546,71.687 8.42,71.724 -28.612,71.91 -36.688,71.923 -0.892,71.931 65.031,71.931 -41.888,71.991 11.975,72.018 14.075,72.018 16.175,72.018 18.275,72.018 20.375,72.018 22.475,72.018 24.575,72.018 26.675,72.018 28.775,72.018 30.875,72.018 32.975,72.018 35.075,72.018 37.175,72.018 39.275,72.018 41.375,72.018 43.475,72.018 45.575,72.018 47.675,72.018 49.775,72.018 51.875,72.018 53.975,72.018 71.625,72.079 -48.932,72.187 -4.912,72.185 56.068,72.188 -30.138,72.234 -6.438,72.376 -23.562,72.472 66.755,72.936 -58.404,72.975 -35.076,72.994 -40.362,73.103 -54.964,73.213 -52.864,73.213 -50.764,73.213 3.274,73.223 9.905,73.209 64.72,73.456 -25.088,73.542 11.978,73.545 14.078,73.545 16.178,73.545 18.278,73.545 20.378,73.545 22.478,73.545 24.578,73.545 26.678,73.545 28.778,73.545 30.878,73.545 32.978,73.545 35.078,73.545 37.178,73.545 39.278,73.545 41.378,73.545 43.478,73.545 45.578,73.545 47.678,73.545 49.778,73.545 51.878,73.545 53.978,73.545 69.006,73.546 57.566,73.66 -57,73.729 -42.842,73.862 70.533,73.873 -29.139,73.943 -31.322,73.968 -36.252,73.978 1.3,74.123 55.966,74.219 -33.402,74.262 -5.165,74.27 -7.331,74.277 -23.162,74.533 -41.611,74.791 -58.713,75.052 -44.327,75.347 5.466,75.415 -30.624,75.428 68.104,75.442 -34.767,75.462 -24.347,75.507 57.572,75.572 8.556,75.669 11.656,75.669 14.756,75.669 17.856,75.669 20.956,75.669 24.056,75.669 27.156,75.669 30.256,75.669 33.356,75.669 36.456,75.669 39.556,75.669 42.656,75.669 45.756,75.669 -21.441,75.737 -19.341,75.737 -17.241,75.737 -15.141,75.737 -13.041,75.737 -10.941,75.737 -8.841,75.737 63.928,75.744 -6.65,75.755 66.028,75.759 -32.692,75.788 -56.733,75.812 69.847,75.858 -54.663,76.162 -52.563,76.162 -50.463,76.162 -48.363,76.162 -46.263,76.162 -43.096,76.275 3.492,76.315 50.361,76.539 -57.774,76.93 -22.862,76.992 -8.181,77.192 65.412,77.229 68.267,77.241 -20.78,77.263 -18.68,77.263 -16.58,77.263 -14.48,77.263 -12.38,77.263 -10.28,77.263 67.512,77.27 -44.676,77.659 5.39,77.655 -55.816,77.688 -53.716,77.688 -51.616,77.688 -49.516,77.688 -47.416,77.688 -45.316,77.688
  other v2: 73.448,-78.959 -73.299,-78.823 -69.5,-78.5 -65.5,-78.5 -61.5,-78.5 -57.5,-78.5 -53.5,-78.5 -49.5,-78.5 -45.5,-78.5 -41.5,-78.5 -37.5,-78.5 -33.5,-78.5 -29.5,-78.5 -25.5,-78.5 -21.5,-78.5 -17.5,-78.5 -13.5,-78.5 -9.5,-78.5 -5.5,-78.5 -1.5,-78.5 2.5,-78.5 6.5,-78.5 10.5,-78.5 14.5,-78.5 18.5,-78.5 22.5,-78.5 26.5,-78.5 30.5,-78.5 34.5,-78.5 38.5,-78.5 42.5,-78.5 46.5,-78.5 50.5,-78.5 54.5,-78.5 58.5,-78.5 62.5,-78.5 66.5,-78.5 70.5,-78.5 72.141,-75.438 -72.225,-75.417 -78.955,-73.415 78.828,-73.322 75.138,-72.336 -74.993,-72.254 68.849,-70.586 57.197,-70.575 -78.5,-70.5 -70.5,-70.5 -66.5,-70.5 -62.5,-70.5 -58.5,-70.5 -54.5,-70.5 -50.5,-70.5 -46.5,-70.5 -42.5,-70.5 -38.5,-70.5 -34.5,-70.5 -30.5,-70.5 -26.5,-70.5 -22.5,-70.5 -18.5,-70.5 -14.5,-70.5 -10.5,-70.5 -6.5,-70.5 -2.5,-70.5 1.5,-70.5 5.5,-70.5 9.5,-70.5 13.5,-70.5 17.5,-70.5 21.5,-70.5 25.5,-70.5 29.5,-70.5 33.5,-70.5 37.5,-70.5 41.5,-70.5 45.5,-70.5 49.5,-70.5 53.5,-70.5 61.5,-70.5 65.5,-70.5 73.175,-70.075 78.5,-69.5 -37.5,-69.001 34.5,-69.001 70.538,-67.39 -34.5,-67.001 37.5,-67.001 1.5,-67 -78.5,-66.5 -70.5,-65.5 78.5,-65.5 -37.5,-65.001 -1.5,-65 34.5,-65.001 -34.5,-63.001 1.5,-63 37.5,-63.001 -78.5,-62.5 70.45,-61.675 -70.5,-61.5 78.5,-61.5 -37.5,-61.001 -1.5,-61 34.5,-60.501 70.475,-59.125 -34.5,-59.001 1.5,-59 37.5,-59.001 -78.5,-58.5 34.5,-57.501 -70.5,-57.5 78.5,-57.5 70.522,-57.44 -37.5,-57.001 -1.5,-57 77.55,-56.925 77.55,-56.025 -34.5,-55.001 1.5,-55 37.5,-55.001 -78.5,-54.5 78.45,-54.325 34.5,-54.001 -70.5,-53.5 70.522,-53.44 77.55,-53.2 -37.5,-53.001 -1.5,-53 77.7,-51.6 -34.5,-51.001 1.5,-51 37.5,-51.001 -78.5,-50.5 34.5,-50.501 -70.5,-49.5 78.5,-49.5 70.522,-49.44 -37.5,-49.001 -1.5,-49 1.5,-47 37.5,-47.001 -78.5,-46.5 78.975,-46.45 70.468,-46.104 -34.5,-46.001 -70.5,-45.5 -37.5,-45.001 34.5,-45.001 37.5,-44.501 -34.5,-43.001 70.475,-43 79.075,-42.9 -0.6,-42.6 -78.5,-42.5 -70.5,-41.5 -37.5,-41.001 34.5,-41.001 0.797,-40.836 78.975,-40.025 70.475,-39.625 0.58,-39.448 -34.5,-39.001 37.5,-39.001 -78.5,-38.5 63.636,-37.519 -70.5,-37.5 -66.999,-37.5 -62.999,-37.5 -58.999,-37.5 -54.999,-37.5 -50.999,-37.5 -45.999,-37.5 -42.999,-37.5 -38.999,-37.5 -34.999,-37.5 -30.999,-37.5 -26.999,-37.5 -22.999,-37.5 -18.999,-37.5 -14.999,-37.5 -10.999,-37.5 5.001,-37.499 9.001,-37.5 13.001,-37.5 17.001,-37.5 21.001,-37.5 25.001,-37.5 29.001,-37.5 33.001,-37.5 37.001,-37.5 41.001,-37.5 45.001,-37.5 49.001,-37.5 53.001,-37.5 57.001,-37.5 60.601,-37.5 79.05,-37.15 75.45,-37.006 -37.5,-37.001 34.5,-37.001 -0.887,-36.884 0.001,-36.884 0.888,-36.884 4.85,-36.851 76.259,-36.744 62.369,-36.504 65.935,-36.412 -6.641,-36.009 -0.887,-35.997 0,-36 0.888,-35.997 -0.887,-35.109 0.001,-35.109 0.888,-35.109 -34.5,-35.001 37.5,-35.001 4.176,-34.954 63.475,-34.581 52.55,-34.525 -78.5,-34.5 -68.999,-34.5 -64.999,-34.5 -60.999,-34.5 -56.999,-34.5 -52.999,-34.5 -48.999,-34.5 -44.999,-34.5 -40.999,-34.5 -36.999,-34.5 -32.999,-34.5 -28.999,-34.5 -24.999,-34.5 -20.999,-34.5 -16.999,-34.5 -12.999,-34.5 7.25,-34.5 11.001,-34.5 15.001,-34.5 19.001,-34.5 23.001,-34.5 27.001,-34.5 31.001,-34.5 35.001,-34.5 39.001,-34.5 43.001,-34.5 47.001,-34.5 55.001,-34.5 59.001,-34.5 -9.2,-34.375 78.525,-34.15 -70.5,-33.5 34.498,-33.128 -37.5,-33.001 0.738,-32.884 0.813,-31.459 -34.5,-31.001 37.5,-31.001 -78.5,-30.5 79.059,-30.145 -0.525,-29.875 -70.5,-29.5 70.475,-29.475 -37.5,-29.001 34.5,-29.001 70.475,-27.875 -34.5,-27.001 1.499,-27 37.5,-27.001 -78.5,-26.5 -70.5,-25.5 78.5,-25.5 -37.5,-25.001 -1.501,-25 34.5,-25.001 70.5,-23.2 -34.5,-23.001 1.499,-23 37.5,-23.001 -78.5,-22.5 -70.5,-21.5 78.5,-21.5 -37.5,-21.001 -1.501,-21 34.5,-21.001 74.645,-20.848 70.5,-19.2 -34.5,-19.001 1.499,-19 37.5,-19.001 -78.5,-18.5 74.645,-18.27 -70.5,-17.5 78.5,-17.5 -37.5,-17.001 -1.501,-17 34.5,-17.001 70.5,-15.2 -34.5,-15.001 1.499,-15 37.5,-15.001 -78.5,-14.5 -70.5,-13.5 78.5,-13.5 -37.5,-13.001 -1.501,-13 34.5,-13.001 70.5,-11.2 -34.5,-11.001 1.499,-11 37.5,-11.001 -78.5,-10.5 -37.5,-10.001 -70.5,-9.5 78.5,-9.5 -1.501,-9 34.5,-9.001 70.5,-7.2 -34.5,-7.001 -78.5,-6.5 -70.5,-5.5 78.5,-5.5 -37.5,-5.001 34.5,-5.001 1.393,-4.654 70.5,-3.2 -34.5,-3.001 37.5,-3.001 -78.5,-2.5 -70.5,-1.5 -67,-1.5 -63,-1.5 -59,-1.5 -55,-1.5 -51,-1.5 -47,-1.5 -43,-1.5 -39,-1.5 -35,-1.5 -31,-1.5 -27,-1.5 -23,-1.5 -19,-1.5 -15,-1.5 -11,-1.5 -7,-1.5 -3,-1.5 1,-1.5 5,-1.5 9,-1.5 13,-1.5 17,-1.5 21,-1.5 25,-1.5 29,-1.5 33,-1.5 37,-1.5 41,-1.5 45,-1.5 49,-1.5 53,-1.5 57,-1.5 63.6,-1.5 78.5,-1.5 -37.501,-1 -1.501,-1 71.5,0.8 -34.501,1 1.499,1 37.499,1 -78.5,1.5 -69,1.5 -65,1.5 -61,1.5 -57,1.5 -53,1.5 -49,1.5 -45,1.5 -41,1.5 -37,1.5 -33,1.5 -29,1.5 -25,1.5 -21,1.5 -17,1.5 -13,1.5 -9,1.5 -5,1.5 -1,1.5 3,1.5 7,1.5 11,1.5 15,1.5 19,1.5 23,1.5 27,1.5 31,1.5 35,1.5 39,1.5 43,1.5 47.5,1.5 51,1.5 55,1.5 59,1.5 62,1.501 67,1.501 -70.5,2.5 78.5,2.5 -37.501,3 -1.501,3 70.5,4.8 -34.501,5 1.499,5 37.499,5 -78.5,5.5 -70.5,6.5 -37.501,7 -1.501,7 34.499,7 78.772,8.527 70.5,8.8 -34.501,9 1.499,9 37.499,9 -78.5,9.5 -1.501,10.25 -70.5,10.5 -37.501,11 34.499,11 78.833,11.124 70.5,12.8 -34.501,13 1.499,13 37.499,13 -78.5,13.5 78.431,13.693 -70.5,14.5 78.5,14.5 -37.501,15 -1.501,15 34.499,15 70.5,16.8 -34.501,17 1.499,17 37.499,17 -78.5,17.5 -70.5,18.5 78.5,18.5 -37.501,19 -1.501,19 34.499,19 -34.501,21 37.499,21 70.415,21.12 -78.5,21.5 1.499,21.6 -70.5,22.5 78.5,22.5 -37.501,23 -1.501,23 34.499,23 -34.501,25 1.499,25 37.499,25 70.415,25.12 -78.5,25.5 -70.5,26.5 78.5,26.5 -37.501,27 -1.501,27 34.499,27 0.006,27.625 -34.501,29 37.499,29 70.415,29.12 -0.001,29.475 -78.5,29.5 -70.5,30.5 78.5,30.5 -37.501,31 34.499,31 -34.501,33 37.499,33 70.415,33.12 -78.5,33.5 65.939,34.425 -70.5,34.5 -67,34.5 -63,34.5 -59,34.5 -55,34.5 -51,34.5 -47,34.5 -43,34.5 -39,34.5 -35,34.5 -31,34.5 -27,34.5 -23,34.5 -19,34.5 -15,34.5 -11,34.5 13.5,34.5 17,34.5 21,34.5 25,34.5 29,34.5 33,34.5 37,34.5 41,34.5 45,34.5 49,34.5 53,34.5 57,34.5 61,34.5 69,34.5 78.5,34.5 -37.501,35 34.499,35 -0.887,35.116 0,35.116 0.888,35.116 -6.375,35.45 -0.887,36.003 0,36 0.888,36.003 3.538,36.566 -3.012,36.666 -3.787,36.716 4.227,36.841 6.85,36.849 -0.887,36.891 0,36.891 0.888,36.891 -34.501,37 37.499,37 -78.5,37.5 -69,37.5 -65,37.5 -61,37.5 -57,37.5 -53,37.5 -49,37.5 -45,37.5 -41,37.5 -37,37.5 -33,37.5 -29,37.5 -25,37.5 -21,37.5 -17,37.5 -13,37.5 -9,37.5 11,37.5 16,37.5 19,37.5 23,37.5 27,37.5 31,37.5 35,37.5 39,37.5 43,37.5 47,37.5 51,37.5 55,37.5 59,37.5 63,37.5 67,37.5 78.65,37.5 -70.5,38.5 70.525,38.825 -37.501,39 34.499,39 -34.501,39.5 78.675,40.5 0.85,40.849 37.499,41 -78.5,41.5 -37.501,41.5 70.4,42.4 -70.5,42.5 -1.501,43 34.499,43 78.725,43.525 -34.501,45 1.499,45 37.499,45 70.423,45.127 -78.5,45.5 78.825,46.35 -70.5,46.5 75.552,46.829 -37.501,47 -1.501,47 34.499,47 70.423,47.127 75.552,48.911 -34.501,49 1.499,49 37.499,49 70.423,49.127 -78.5,49.5 78.925,49.575 -70.5,50.5 70.423,50.82 -37.501,51 -1.501,51 75.552,51.058 34.499,52 79.025,52.675 -34.501,53 1.499,53 37.499,53 -78.5,53.5 70.423,53.587 75.552,54.032 -70.5,54.5 70.423,54.65 -37.501,55 -1.501,55 34.499,55 79.125,55.4 -34.501,57 1.499,57 37.499,57 75.552,57.253 -78.5,57.5 70.423,57.503 79.1,58.35 -70.5,58.5 -37.501,59 -1.501,59 34.499,59 70.423,59.127 75.552,59.401 -34.501,61 1.499,61 37.499,61 70.423,61.127 -78.5,61.5 75.552,61.614 79.083,61.77 -70.5,62.5 -37.501,63 -1.501,63 34.499,63 70.423,63.127 70.423,64.495 78.5,64.5 -34.501,65 -78.5,65.5 37.499,65.5 1.487,66.266 70.443,66.279 34.546,66.412 -70.5,66.5 78.5,66.5 -37.501,67 -1.501,67 75.27,68.461 -34.501,69 35.781,69.227 70.45,69.325 -78.5,69.5 -70.5,70.5 -66.5,70.5 -62.5,70.5 -58.5,70.5 -54.5,70.5 -50.5,70.5 -46.5,70.5 -42.5,70.5 -38.5,70.5 -34.5,70.5 -30.5,70.5 -26.5,70.5 -22.5,70.5 -18.5,70.5 -14.5,70.5 -10.5,70.5 -6.5,70.5 -2.5,70.5 1.5,70.5 5.5,70.5 10.175,70.5 13.5,70.5 17.5,70.5 21.5,70.5 25.5,70.5 29.5,70.5 33.5,70.5 37.5,70.5 41.5,70.5 45.5,70.5 49.5,70.5 53.5,70.5 57.5,70.5 61.5,70.5 65.5,70.5 69.5,70.5 78.5,70.5 -75.321,72.118 75.365,72.209 62.605,72.475 -78.886,73.249 78.765,73.444 72.119,75.184 -72.122,75.479 59.099,77.488 -69.5,78.5 -65.5,78.5 -61.5,78.5 -57.5,78.5 -53.5,78.5 -49.5,78.5 -45.5,78.5 -41.5,78.5 -37.5,78.5 -33.5,78.5 -29.5,78.5 -25.5,78.5 -21.5,78.5 -17.5,78.5 -13.5,78.5 -9.5,78.5 -5.5,78.5 -1.5,78.5 2.5,78.5 6.5,78.5 10.5,78.5 14.5,78.5 18.5,78.5 22.5,78.5 26.5,78.5 30.5,78.5 34.5,78.5 38.5,78.5 42.5,78.5 46.5,78.5 50.5,78.5 54.5,78.5 58.5,78.5 62.5,78.5 66.5,78.5 70.5,78.5 -73.504,78.959 73.473,78.951
  other v3: 57.166,-73.37 60.259,-72.609 58.97,-70.278 68.264,-69.435 73.805,-69.296 75.278,-68.904 66.948,-68.338 58.897,-67.259 75.953,-66.02 69.057,-65.725 60.087,-64.879 66.48,-64.891 63.13,-64.817 57.608,-64.29 59.142,-63.284 67.498,-62.903 64.492,-62.817 60.59,-62.204 57.964,-61.787 62.958,-61.149 58.148,-59.541 61.167,-59.492 59.78,-59.026 69.393,-58.509 71.747,-57.494 70.348,-55.134 72.446,-54.912 66.175,-46.326 77.2,-44.566 62.241,-44.471 68.508,-44.488 74.831,-44.452 65.108,-44.4 -2.46,-43.681 -4.105,-43.442 -2.037,-42.284 -5.683,-42.248 -3.287,-41.709 62.268,-41.604 77.32,-41.602 66.2,-41.081 -6.851,-41.033 -4.387,-40.884 72.375,-40.825 74.598,-39.97 -5.312,-39.859 73.874,-39.814 -7.699,-39.348 -5.987,-38.659 67.4,-37.931 72.075,-37.831 -8.124,-37.702 65.525,-37.681 -6.387,-37.359 3.86,-37.255 65.55,-37.075 64.475,-36.5 -8.265,-35.953 64.3,-34.831 65.4,-34.806 -6.412,-34.634 -8.085,-34.294 64.675,-34.256 65.4,-34.206 62.85,-33.981 2.944,-33.808 -5.987,-33.334 -7.545,-32.648 62.237,-32.475 -5.287,-32.159 72.174,-32.097 77.225,-31.225 -4.362,-31.159 -6.651,-31.091 -3.287,-30.309 69.4,-30.25 75.1,-30.2 77.225,-30.2 -5.385,-29.87 -2.012,-29.809 68.991,-29.534 2.075,-29.433 -3.931,-29.034 -0.625,-28.475 -2.388,-28.43 77.024,-23.476 72.067,-23.14 62.972,-0.25 60.36,0.437 62.644,2.029 73.168,4.925 75.398,5.51 73.368,6.925 75.662,8.634 73.664,8.892 75.398,10.699 73.35,11.95 -1.71,27.871 1.702,27.876 3.348,28.3 -3.352,28.454 5.033,29.149 -4.775,29.4 -1.362,29.591 1.363,29.591 -2.662,30.016 2.663,30.016 6.247,30.316 -6.094,30.515 3.956,30.593 -3.837,30.716 5.136,31.397 -4.862,31.616 -6.966,32.068 5.888,32.619 -5.687,32.716 -7.571,33.612 6.263,33.966 -6.175,34 5.28,35.659 72.448,38.899 1.173,39.855 71.761,42.954 73.975,65.425 72.375,65.55 69.127,66.09
N16816371: L201.1 U1.31
N16816400: C217.1 U1.30 | length 0.8
  Bottom Layer w0.2: U1.30@71.55,-32.455 C217.1@71.55,-31.65
N16816410: U1.9 X1.3 | length 1.6
  Bottom Layer w0.1: X1.3@68.291,-38.891 68.15,-38.75 68.15,-38.477 68.15,-37.95 68.35,-37.75 U1.9@68.35,-37.445
N16816441: U1.10 X1.1 | length 2.5
  Bottom Layer w0.1: X1.1@67.7,-40.025 67.9,-39.825 67.9,-38.56 U1.10@67.9,-37.667 ; U1.10@67.925,-37.642 U1.10@67.95,-37.667
N16816744: C204.1 C205.1 L202.2 U1.12 | length 2.8
  Bottom Layer w0.2: C204.1@66.525,-37 66.51,-36.985 66.51,-36.69 66.85,-36.35 U1.12@67.255,-36.35
  Bottom Layer w0.25: L202.2@66.05,-38.425 66.525,-37.95 C205.1@66.525,-37.55 66.525,-37.038 C204.1@66.544,-37.019
N16816775: C206.1 C207.1 L203.2 U1.15 | length 3.5
  Bottom Layer w0.2: C206.1@66.45,-34.881 66.45,-34.963 66.638,-35.151 U1.15@67.255,-35.151
  Bottom Layer w0.3: L203.2@65,-33.575 65.95,-33.575 66.45,-34.075 C206.1@66.45,-34.906
N16857153: CC11.2 D11.2 U201.3 | length 2.7
  Bottom Layer w0.28: U201.3@74.45,21.929 75.838,23.317 CC11.2@75.838,24.054
N16857156: CC12.2 D12.2 U201.1 | length 2.7
  Bottom Layer w0.28: CC12.2@71.212,24.074 71.212,23.267 U201.1@72.55,21.929
N16857328: H1.2 RH1.1 | length 0.8
  Bottom Layer w0.35: H1.2@73.185,63.746 RH1.1@73.185,64.56
N16857331: CH1.1 LH1.1 R209.1 | length 1.5
  Bottom Layer w0.28: R209.1@69.567,38.789 CH1.1@69.567,39.753 ; CH1.1@69.567,39.753 LH1.1@69.567,40.303
N16857342: CH2.1 LH1.2 R211.1 | length 1.9
  Bottom Layer w0.28: R211.1@68.22,41.45 69.565,41.45 CH2.1@69.567,41.453 LH1.2@69.567,40.903
N16857347: CH2.2 CH4.1 LH2.2 | length 1.2
  Bottom Layer w0.28: CH2.2@70.117,41.453 70.417,41.453 ; LH2.2@70.417,40.903 70.417,41.453 ; CH4.1@70.717,41.453 70.417,41.453
N16857354: CH1.2 CH3.1 LH2.1 | length 1.2
  Bottom Layer w0.28: CH1.2@70.117,39.753 70.417,39.753 ; LH2.1@70.417,40.303 70.417,39.753 ; CH3.1@70.717,39.753 70.417,39.753
N16857397: CH4.2 LH3.2 R213.1 | length 1.9
  Bottom Layer w0.28: LH3.2@71.267,40.903 CH4.2@71.267,41.453 R213.1@72.62,41.453
N16857402: H1.4 R210.1 | length 2.3
  Bottom Layer w0.28: R210.1@67.32,42.35 67.655,42.685 H1.4@67.655,44.546
N16857405: H1.3 R212.1 | length 2.3
  Bottom Layer w0.28: H1.3@73.185,44.546 73.185,42.685 R212.1@73.52,42.35
N16857668: CC31.1 D31.2 U203.3 | length 2.7
  Bottom Layer w0.28: U203.3@62.809,73.875 63.991,72.692 CC31.1@65.02,72.692
N16857679: CC32.1 D32.2 U203.1 | length 2.7
  Bottom Layer w0.28: U203.1@62.809,75.775 63.531,76.497 63.541,76.507 CC32.1@65.206,76.507
N16857715: CC41.1 D41.2 U204.3 | length 2.7
  Bottom Layer w0.28: U204.3@63.169,-2.552 64.841,-2.552 CC41.1@65.568,-1.825
N16857764: CC42.1 D42.2 U204.1 | length 2.7
  Bottom Layer w0.28: U204.1@61.825,-1.209 61.825,-0.769 61.825,-0.188 61.825,-0.173 61.83,-0.168 CC42.1@63.002,1.004
N16857781: CC33.2 D33.2 U203.5 | length 2.4
  Bottom Layer w0.28: CC33.2@58.551,74.825 U203.5@60.951,74.825
N16857793: L11.2 U205.3 | length 1.6
  Bottom Layer w0.2: U205.3@-0.625,38.01 L11.2@-0.625,39.625
N16857806: R214.1 R215.2 U205.6 | length 1.7
  Bottom Layer w0.2: R214.1@0.45,39.05 0.6,38.9 U205.6@0.6,37.985
  Bottom Layer w0.28: R214.1@0.45,39.05 R215.2@0.45,39.625
N16857833: R214.2 U205.4 | length 1.1
  Bottom Layer w0.2: U205.4@-0.2,37.985 -0.2,38.937 R214.2@-0.087,39.05
N16857836: CC43.2 D43.2 U204.5 | length 2.4
  Bottom Layer w0.28: CC43.2@59.486,-4.891 U204.5@61.183,-3.195
N16857848: L21.2 U206.3 | length 1.5
  Bottom Layer w0.2: U206.3@1.985,-35.4 L21.2@3.497,-35.4
N16857851: R216.1 R217.2 U206.6 | length 1.6
  Bottom Layer w0.2: U206.6@1.985,-36.6 2.778,-36.6 R216.1@2.922,-36.456 R216.1@2.928,-36.45
  Bottom Layer w0.28: R216.1@2.928,-36.45 R217.2@3.497,-36.45
N16857888: R216.2 U206.4 | length 1
  Bottom Layer w0.2: U206.4@1.985,-35.8 2.816,-35.8 R216.2@2.922,-35.906
N17007322: CH3.2 LH3.1 RH2.1 | length 1.2
  Bottom Layer w0.28: LH3.1@71.267,40.303 CH3.2@71.267,39.753 RH2.1@71.867,39.753
N17033218: LED1.2 R202.2 | length 1.2
  Bottom Layer w0.2: R202.2@74.625,-51.575 LED1.2@75.85,-51.575
N17041538: C222.2 R207.2 U208.1 | length 2
  Bottom Layer w0.1: U208.1@74.355,5.973 74.354,5.971 C222.2@74.354,4.759 R207.2@75.143,4.759
N17041550: C221.2 R206.2 U207.1 | length 2.1
  Bottom Layer w0.1: U207.1@74.355,10.973 C221.2@74.355,9.639 R206.2@75.105,9.639
PAVDD: L203.1 R203.1 R204.2 | length 16
  Bottom Layer w0.3: L203.1@65,-31.925 L203.1@65,-31.9 65,-30.2 66.1,-29.1 66.1,-27.3 69.025,-24.375 73.092,-24.375 73.392,-24.675 75.414,-24.675 R203.1@75.571,-24.833
TP_TDI: TPJ4.1
VDCDC: C215.1 C216.1 L201.2 L202.1 R204.1 U1.34 | length 34.8
  IM3 Signal w0.5: v2(74.772,-23.925) 77.975,-27.128 77.975,-31.25 v2(77.05,-32.175)
  IM3 Signal w0.6: v2(77.05,-32.806) v2(77.05,-32.175)
  IM2 Signal w0.4: v2(64.353,-37.202) 64.353,-36.447 65.099,-35.701 71.149,-35.701 72.326,-34.524 72.326,-34.15 ; v2(73.075,-34.15) 72.326,-34.15 ; v2@77.05,-32.2 73.401,-32.2 72.326,-33.275 72.326,-34.15
  IM2 Signal w0.6: v2(77.05,-32.806) v2(77.05,-32.175)
  Bottom Layer w0.2: U1.34@72.245,-34.35 72.772,-34.35 v2@73.024,-34.098 ; v2(73.075,-34.15) C216.1@73.475,-34.15 ; v2@73.15,-34.075 C216.1@73.45,-34.075
  Bottom Layer w0.5: v2(64.353,-37.202) 64.353,-38.478 L202.1@64.425,-38.55 ; v2(74.772,-23.925) R204.1@75.575,-23.925 ; v2(77.05,-32.806) v2@77.081,-32.806
  Bottom Layer w0.6: L201.2@76.225,-31.125 76.225,-32 76.325,-32.1 76.975,-32.1 v2(77.05,-32.175) v2(77.05,-32.806) C215.1@77.05,-33.475
VMCU: C202.1 C203.1 C209.1 C210.1 C211.1 C212.1 C213.1 C214.1 C218.1 C219.2 C220.2 C223.2 C224.2 J201.1 R201.2 R202.1 R203.2 R205.2 TPJ11.1 U1.32 U1.35 U1.36 U200.A1 U200.E3 U205.1 U205.32 U206.1 U206.32 U207.5 U208.5 | length 438.6
  IM3 Signal w0.3: v2(35.675,-40.275) 35.675,-33.475 35.375,-33.175 35.375,-31.775 v2(35.875,-31.275)
  IM2 Signal w0.4: J201.1@36.91,-76.45 38.935,-74.425 70.2,-74.425 72.382,-72.243 v2(72.382,-69.164) 74.653,-69.164 75.469,-68.347 v2(75.469,-53.137) ; v2(71.225,-40.05) 72.15,-40.05 ; v2(72.15,-42.875) 72.15,-40.05 ; v2(75.475,-52.486) 77.28,-50.682 v2@77.28,-40.05 ; v2(76.229,-34.552) 76.368,-34.552 76.37,-34.55 v2@76.372,-34.552 ; 76.925,-34.55 76.927,-34.552 77.28,-34.905 v2@77.28,-40.05 ; v2(77.3,-40.05) v2@77.28,-40.05 ; 72.15,-40.05 v2@77.28,-40.05
  IM2 Signal w0.5: v2(49.4,76.975) 55.428,76.975 57.783,74.62 67.293,74.62 73.72,68.192 73.72,45.748 75.816,43.651 75.816,33.825 77.531,32.109 77.531,29.93 76.763,29.161 76.763,14.993 77.675,14.081 v2(77.675,9.85) v2(77.675,4.875) 77.675,3.267 76.611,2.203 76.611,-24.036 v2@77.463,-24.888 ; v2(73.1,-34.881) 74.046,-34.881 ; v2(73.625,-33.575) 73.65,-33.575 74.046,-33.97 74.046,-34.881 ; 75.35,-34.889 75.475,-35.014 v2(75.475,-36.225) ; v2(76.229,-34.552) 76.079,-34.552 75.75,-34.881 74.046,-34.881 ; v2@76.368,-34.552 76.372,-34.552 76.927,-34.552 76.973,-34.552 78.225,-33.3 78.225,-27.25 ; v2(77.463,-24.859) v2@77.463,-24.888 ; v2@77.463,-24.888 77.475,-24.9 77.475,-26.5 77.525,-26.55 ; 77.525,-26.55 78.225,-27.25 ; 77.525,-26.55 78.225,-27.25
  IM2 Signal w0.6: v2(75.469,-53.137) 75.469,-52.492 v2(75.475,-52.486)
  Bottom Layer w0.2: R205.2@70.225,-41.425 70.225,-40.925 70.475,-40.675 C218.1@71.225,-40.675 ; v2(71.225,-40.05) C218.1@71.225,-40.675 ; U200.A1@71.25,-41.425 C218.1@71.25,-40.675 C218.1@71.225,-40.675 ; U200.E3@72.05,-42.125 72.15,-42.225 v2@72.15,-42.85 ; U1.35@72.245,-34.75 72.82,-34.75 ; U1.32@72.245,-33.55 73.05,-33.55 ; U1.36@72.35,-35.15 72.639,-35.15 73.025,-35.536 73.025,-35.681 73.375,-36.031 C213.1@74.1,-36.031 C214.1@74.675,-36.031 ; C209.1@73.075,-32.981 73.05,-33.006 73.05,-33.55 ; C212.1@73.4,-35.15 73.4,-34.8 C211.1@73.475,-34.725 ; C211.1@73.425,-34.75 72.82,-34.75 ; C212.1@73.575,-35.375 73.445,-35.375 72.82,-34.75 ; v2(73.625,-33.575) v2@73.675,-33.575 ; v2@73.65,-33.55 73.05,-33.55
  Bottom Layer w0.3: -2.25,37.741 -2.25,37.804 ; -2.25,37.975 -2.25,37.954 ; -1.987,37.666 -2.112,37.666 -2.25,37.804 ; 1.726,-33.947 C224.2@2.748,-32.925 ; C224.2@2.563,-33.009 3.173,-32.4 34.75,-32.4 v2(35.875,-31.275) ; v2(35.675,-40.275) 36.075,-40.675 57.225,-40.675 58.45,-41.9 58.45,-46.275 61.95,-49.775 68.45,-49.775 71.161,-52.486 v2(75.475,-52.486) ; v2(49.4,76.975) 5.175,76.975 -3.448,68.352 -3.448,39.151 -2.25,37.954 ; R201.2@75.475,-56.037 C202.1@76.375,-56.037 ; U208.5@76.895,6.925 78.093,6.925 C220.2@78.097,6.928 78.097,5.297 v2(77.675,4.875) ; U207.5@76.895,11.925 78.075,11.925 C219.2@78.078,11.921 78.078,10.253 v2(77.675,9.85) ; -2.25,37.804 -2.25,37.954
  Bottom Layer w0.4: TPJ11.1@68.949,-67.907 70.206,-69.164 v2(72.382,-69.164) ; v2@75.469,-52.492 v2(75.475,-52.486)
  Bottom Layer w0.5: C214.1@74.8,-36.231 74.825,-36.206 74.845,-36.225 v2(75.475,-36.225) ; R201.2@75.475,-56.037 C203.1@75.475,-54.462 v2@75.475,-53.137 ; C210.1@75.65,-34.656 75.975,-34.656 76.081,-34.55 76.083,-34.552 v2(76.229,-34.552) ; R203.2@76.606,-24.859 v2(77.463,-24.859)
  Bottom Layer w0.6: v2(75.469,-53.137) v2@75.469,-52.492
VMCU_IN: C201.1 P201.1 R201.1 | length 2.6
  Bottom Layer w0.3: R201.1@75.475,-56.937 C201.1@76.375,-56.937
  Bottom Layer w0.5: R201.1@75.475,-56.937 75.475,-58.33 P201.1@75.657,-58.512
VRF: TPJ9.1
pads on no net: Hole1.1 Hole2.1 Hole3.1 Hole4.1 TPJ18.1 TPJ19.1 U200.C1 U205.10 U205.12 U205.29 U205.30 U205.31 U206.10 U206.12 U206.29 U206.30 U206.31

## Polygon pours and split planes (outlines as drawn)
GND on IM4 GND "L3_GND" (solid, pour order 0): -80,80 80,80 80,-80 -80,-80
GND on IM3 Signal "L2_CELL_FILL" (solid, remove dead copper, pour order 2): -80,80 80,80 80,-80 -80,-80
GND on Top Layer "Top_GND" (solid, pour order 8): -80,80 80,80 80,-80 -80,-80
GND on IM2 Signal "GND_L03_P010" (solid, remove dead copper, pour order 10): -80,80 -80,-80 80,-80 80,80
GND on IM1 RIS "GND_L02_P012" (solid, pour order 12): -80,80 -80,-80 80,-80 80,80
GND on Bottom Layer "Bottom_GND" (solid, remove dead copper, pour order 6): -80,80 80,80 80,-80 -80,-80

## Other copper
IM4 GND:
  pour cut-out: 77.493,-20.342 77.493,-18.642 75.389,-18.642 75.389,-18.91 74.093,-18.911 74.093,-20.079 75.389,-20.079 75.389,-20.341
Bottom Layer:
  region net GND: 62.822,76.439 63.59,77.206 63.571,77.341 62.937,77.975 62.142,77.18 62.142,77.038
  region net GND: 60.144,74.315 59.055,74.315 58.999,74.228 58.999,73.358 60.165,73.358 60.218,73.411
  region net GND: 63.191,72.772 63.958,72.005 63.907,71.902 63.312,71.307 62.499,72.12 62.499,72.226
  region net VMCU: 2.05,-33.6 1.325,-33.6 1.325,-34.35 1.65,-34.675 2.125,-34.675 2.125,-33.675
  pour cut-out: 67.33,-35.125 67.33,-35.975 62.765,-35.975 62.765,-35.125
  region net GND: 64.219,-3.062 65.303,-3.062 65.34,-3.172 65.34,-4.013 64.19,-4.013 64.115,-3.938
  region net GND: 70.48,23.278 71.636,22.122 71.262,21.725 70.771,21.725 69.792,22.704
  region net GND: 72.991,19.24 72.991,18.11 72.819,18.051 71.952,18.051 71.952,19.176 72.052,19.276
  region net GND: 60.973,-4.125 60.203,-4.896 60.225,-4.997 60.84,-5.613 61.665,-4.788 61.665,-4.713
  region net GND: 61.365,-0.73 61.365,0.355 61.256,0.437 60.36,0.437 60.36,-0.688 60.46,-0.788
  region net GND: 74.964,34.039 75.738,34.813 75.235,35.274 74.964,35.274 74.31,34.62
  region net GND: 74.01,29.982 74.01,28.892 75.004,28.872 75.144,29.013 75.144,29.826
  region net GND: 72.104,33.969 71.333,34.74 71.355,34.875 71.825,35.345 72.178,35.345 72.85,34.673
  region net N16816371: 74.325,-30.006 73.45,-30.006 73.45,-31.425 71.85,-33.025 71.85,-33.3 72.65,-33.3 72.65,-32.95 73.22,-32.381 74.325,-32.381
  pour cut-out: 72.85,-32.7 72.85,-37.45 74.3,-37.45 74.3,-37.65 75.15,-37.65 75.15,-35.775 75.675,-35.25 76.6,-35.25 76.6,-32.7
  region net GND: 75.44,22.197 76.556,23.314 76.764,23.314 77.377,22.701 76.326,21.65 75.919,21.65
  pour cut-out: 66.452,-39.325 66.452,-39.628 66.75,-39.926 66.75,-41.025 66.8,-41.075 67.62,-41.075 68.29,-41.745 69,-41.745 69,-41.031 69,-38.25 67.125,-38.25 66.8,-38.575 66.8,-38.977
  region net VMCU: -2.4,38.05 -2.4,37.325 -1.65,37.325 -1.325,37.65 -1.325,38.125 -2.325,38.125
  pour cut-out: 72.142,41.985 68.779,41.985 68.779,39.27 72.142,39.27
  region net GND: 66.125,-36.539 65.275,-36.539 65.275,-37.975 65.8,-37.975 66.125,-37.975 66.125,-37.65
  pour cut-out: 0,-40.5 cw(c0,-36) 0,-31.5
  pour cut-out: 4.5,36 cw(c0,36) -4.5,36
  region net GND: 66.075,-34.131 65.875,-33.931 64.25,-33.931 64.25,-35.125 66.025,-35.125 ccw(c66.026,-35.075) 66.075,-35.075
Multi-Layer:
  pour cut-out: 74.8,74.8 74.8,80 80,80 80,74.8
  pour cut-out: -74.8,74.8 -80,74.8 -80,80 -74.8,80
  pour cut-out: -74.8,-74.8 -74.8,-80 -80,-80 -80,-74.8
  pour cut-out: 74.8,-74.8 80,-74.8 80,-80 74.8,-80

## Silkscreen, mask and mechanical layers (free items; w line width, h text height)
Top Overlay:
  text "90°" at 1.344,71.525 h4.5 r90
  text "45°" at 72.95,67.5 h4.5 r90
  text "135°" at -70.275,65.575 h4.5 r90
  text "1" at -52.75,53.702 h2.5 r90
  text "2" at -16.75,53.167 h2.5 r90
  text "3" at 19.25,53.167 h2.5 r90
  text "4" at 55.25,53.107 h2.5 r90
  text "6" at -16.75,17.226 h2.5 r90
  text "5" at -52.75,17.167 h2.5 r90
  text "7" at 19.25,17.167 h2.5 r90
  text "8" at 55.25,17.167 h2.5 r90
  text "0°" at 77.5,-1.655 h4.5 r90
  text ".2G4power" at -28.725,-2.325 h1.9 r90
  text ".2G4freq" at -30.525,-2.925 h1.9 r90
  text "180°" at -74.775,-3.713 h4.5 r90
  text ".ProcessorType" at -32.35,-14.875 h1.9 r90
  text "9" at -52.75,-18.774 h2.5 r90
  text "11" at 19.25,-19.214 h2.5 r90
  text "Direction Finding Antenna Array" at -35.425,-19.55 h3.2 r90
  text "10" at -16.75,-19.75 h2.5 r90
  text "12" at 55.25,-19.75 h2.5 r90
  text "16" at 55.25,-55.69 h2.5 r90
  text "13" at -52.75,-55.75 h2.5 r90
  text "15" at 19.25,-55.75 h2.5 r90
  text "14" at -16.75,-55.809 h2.5 r90
  text "-135°" at -70.275,-73 h4.5 r90
  text "-45°" at 73,-73 h4.5 r90
  text "VMCU" at 37.215,-75 h1 r45
  text "GND" at 39.755,-75 h1 r45
  text "VCOM_TX" at 42.248,-75 h1 r45
  text "VCOM_RX" at 44.788,-75 h1 r45
  text "VCOM_RTS" at 47.328,-75 h1 r45
  text "VCOM_CTS" at 49.868,-75 h1 r45
  text "CTRL1" at 52.455,-75 h1 r45
  text "CTRL2" at 54.998,-75 h1 r45
  text "CTRL3" at 57.538,-75 h1 r45
  text "CTRL4" at 60.078,-75 h1 r45
  text "CTRL5" at 62.618,-75 h1 r45
  text "CTRL6" at 65.158,-75 h1 r45
  text "CTRL7" at 67.698,-75 h1 r45
  text "-90°" at 1.344,-77 h4.5 r90
Bottom Overlay:
  lines w0.15: -75.448,-8.577 -75.448,-9.577 -74.448,-9.577 ; -75.448,8.423 -75.448,9.423 -74.448,9.423 ; -70.45,-9.475 -69.45,-9.475 -69.45,-8.475 ; -70.45,9.525 -69.45,9.525 -69.45,8.525
  lines w0.152: 66.825,42.55 66.825,42.85 67.125,42.85 ; 66.85,41.65 66.85,41.95 ; 66.875,41.05 66.875,40.95 67.125,40.95 ; 67.525,40.95 67.775,40.95 67.775,41.05 ; 67.525,42.85 67.825,42.85 67.825,42.55 ; 67.825,42.25 67.825,41.95 68.125,41.95 ; 68.425,40.95 68.725,40.95 68.725,41.25 ; 68.425,41.95 68.725,41.95 68.725,41.65 ; 69.075,39 69.075,39.3 69.375,39.3 ; 69.1,38.1 69.1,38.4 ; 69.125,37.5 69.125,37.4 69.375,37.4 ; 69.775,37.4 70.025,37.4 70.025,37.5 ; 69.775,39.3 70.075,39.3 70.075,39 ; 70.075,38.7 70.075,38.4 70.375,38.4 ; 70.675,37.4 70.975,37.4 70.975,37.7 ; 70.675,38.4 70.975,38.4 70.975,38.1 ; 72.125,41.25 72.125,40.95 72.425,40.95 ; 72.125,41.65 72.125,41.95 72.425,41.95 ; 72.725,41.95 73.025,41.95 73.025,42.25 ; 73.025,40.975 73.325,40.975 ; 73.025,42.55 73.025,42.85 73.325,42.85 ; 73.725,42.85 74.025,42.85 74.025,42.55 ; 73.925,41 74.025,41 74.025,41.25 ; 73.925,41.9 74.025,41.9 74.025,41.65 ; 75.082,-23.714 75.082,-23.414 75.382,-23.414 ; 75.107,-24.614 75.107,-24.314 ; 75.132,-25.214 75.132,-25.314 75.382,-25.314 ; 75.782,-25.314 76.032,-25.314 76.032,-25.214 ; 75.782,-23.414 76.082,-23.414 76.082,-23.714 ; 76.082,-24.014 76.082,-24.314 76.382,-24.314 ; 76.682,-25.314 76.982,-25.314 76.982,-25.014 ; 76.682,-24.314 76.982,-24.314 76.982,-24.614
  text "HYBRID_I" at 65.7,48.525 h1.6 r90
  text "HYBRID_Q" at 77.45,48.4 h1.6 r90
  text "QWAVE" at 74.975,45.675 h1.2 r90
  text "QWAVE" at 66.625,45.575 h1.2 r90
  text "LUMPED" at 77.075,39.95 h1.2
  text "LUMPED" at 68.7,39.875 h1.2
  text "LUMPED" at 68.779,39.27 h1.2 r90
  text "HYBRID_IN" at 68.325,38.475 h1.6 r90
  text "QWAVE" at 73.175,36.25 h1.2
  text "BOARD INFO" at -75.798,9.473 h1.6 r90
  text "'.BoardName' Rev. '.BoardRevision'" at -77.275,9.45 h1.52 r90
  text "PAVDD" at 73.9,-21.075 h1.6 r90
  text "VDCDC" at 74.8,-22.475 h1.2 r90
  text "VMCU" at 78.275,-26.425 h1.2
Top Solder:
  the board outline again, w1.2
Bottom Solder:
  the board outline again, w1.2
Mechanical 1:
  the board outline again, w0.1
Drawing Top:
  drawing of 232 lines, arcs and shapes, not listed
Drawing RIS:
  drawing of 1000 lines, arcs and shapes, not listed
Mechanical 7:
  drawing of 2118 lines, arcs and shapes, not listed
  text "TP12" at -80.195,72.421 h0.5
  text "TP12" at -30.395,72.421 h0.5
  text "TP12" at 19.405,72.421 h0.5
  text "TP12" at 69.205,72.421 h0.5
  text "TP2" at -88.046,71.85 h0.5
  text "TP2" at -38.246,71.85 h0.5
  text "TP2" at 11.554,71.85 h0.5
  text "TP2" at 61.354,71.85 h0.5
  text "TP8" at -90.546,71.37 h0.5
  text "TP8" at -40.746,71.37 h0.5
  text "TP8" at 9.054,71.37 h0.5
  text "TP8" at 58.854,71.37 h0.5
  text "TP15" at -79.796,69.77 h0.5
  text "TP15" at -29.996,69.77 h0.5
  text "TP15" at 19.804,69.77 h0.5
  text "TP15" at 69.604,69.77 h0.5
  text "TP6" at -87.127,69.041 h0.5
  text "TP6" at -37.327,69.041 h0.5
  text "TP6" at 12.473,69.041 h0.5
  text "TP6" at 62.273,69.041 h0.5
  text "TP7" at -89.657,69 h0.5
  text "TP7" at -39.857,69 h0.5
  text "TP7" at 9.943,69 h0.5
  text "TP7" at 59.743,69 h0.5
  text "TP14" at -79.796,67.171 h0.5
  text "TP14" at -29.996,67.171 h0.5
  text "TP14" at 19.804,67.171 h0.5
  text "TP14" at 69.604,67.171 h0.5
  text "TP5" at -90.596,66.671 h0.5
  text "TP5" at -40.796,66.671 h0.5
  text "TP5" at 9.004,66.671 h0.5
  text "TP5" at 58.804,66.671 h0.5
  text "TP4" at -87.127,66.521 h0.5
  text "TP4" at -37.327,66.521 h0.5
  text "TP4" at 12.473,66.521 h0.5
  text "TP4" at 62.273,66.521 h0.5
  text "TP10" at -80.696,64.22 h0.5
  text "TP10" at -30.896,64.22 h0.5
  text "TP10" at 18.904,64.22 h0.5
  text "TP10" at 68.704,64.22 h0.5
  text "TP17" at -90.596,64.07 h0.5
  text "TP17" at -40.796,64.07 h0.5
  text "TP17" at 9.004,64.07 h0.5
  text "TP17" at 58.804,64.07 h0.5
  text "TP11" at -79.774,61.667 h0.5
  text "TP11" at -29.974,61.667 h0.5
  text "TP11" at 19.826,61.667 h0.5
  text "TP11" at 69.626,61.667 h0.5
  text "TP13" at -81.546,60.171 h0.5
  text "TP13" at -31.746,60.171 h0.5
  text "TP13" at 18.054,60.171 h0.5
  text "TP13" at 67.854,60.171 h0.5
  text "TP9" at -78.295,59.47 h0.5
  text "TP9" at -28.495,59.47 h0.5
  text "TP9" at 21.305,59.47 h0.5
  text "TP9" at 71.105,59.47 h0.5
  text "TP3" at -88.445,58.271 h0.5
  text "TP3" at -38.645,58.271 h0.5
  text "TP3" at 11.155,58.271 h0.5
  text "TP3" at 60.955,58.271 h0.5
  text "TP18" at -97.995,56.391 h0.5
  text "TP18" at -48.195,56.391 h0.5
  text "TP18" at 1.605,56.391 h0.5
  text "TP18" at 51.405,56.391 h0.5
  text "TP1" at -88.397,55.721 h0.5
  text "TP16" at -81.897,55.721 h0.5
  text "TP1" at -38.597,55.721 h0.5
  text "TP16" at -32.097,55.721 h0.5
  text "TP1" at 11.203,55.721 h0.5
  text "TP16" at 17.703,55.721 h0.5
  text "TP1" at 61.003,55.721 h0.5
  text "TP16" at 67.503,55.721 h0.5
  text "TP19" at -100.147,55.37 h0.5
  text "TP19" at -50.347,55.37 h0.5
  text "TP19" at -0.547,55.37 h0.5
  text "TP19" at 49.253,55.37 h0.5
  text "TP20" at -102.806,48.421 h0.5
  text "TP20" at -53.006,48.421 h0.5
  text "TP20" at -3.206,48.421 h0.5
  text "TP20" at 46.594,48.421 h0.5
  text "TP12" at -80.195,7.621 h0.5
  text "TP12" at -30.395,7.621 h0.5
  text "TP12" at 19.405,7.621 h0.5
  text "TP12" at 69.205,7.621 h0.5
  text "TP2" at -88.046,7.05 h0.5
  text "TP2" at -38.246,7.05 h0.5
  text "TP2" at 11.554,7.05 h0.5
  text "TP2" at 61.354,7.05 h0.5
  text "TP8" at -90.546,6.57 h0.5
  text "TP8" at -40.746,6.57 h0.5
  text "TP8" at 9.054,6.57 h0.5
  text "TP8" at 58.854,6.57 h0.5
  text "TP15" at -79.796,4.97 h0.5
  text "TP15" at -29.996,4.97 h0.5
  text "TP15" at 19.804,4.97 h0.5
  text "TP15" at 69.604,4.97 h0.5
  text "TP6" at -87.127,4.241 h0.5
  text "TP6" at -37.327,4.241 h0.5
  text "TP6" at 12.473,4.241 h0.5
  text "TP6" at 62.273,4.241 h0.5
  text "TP7" at -89.657,4.2 h0.5
  text "TP7" at -39.857,4.2 h0.5
  text "TP7" at 9.943,4.2 h0.5
  text "TP7" at 59.743,4.2 h0.5
  text "TP14" at -79.796,2.371 h0.5
  text "TP14" at -29.996,2.371 h0.5
  text "TP14" at 19.804,2.371 h0.5
  text "TP14" at 69.604,2.371 h0.5
  text "TP5" at -90.596,1.871 h0.5
  text "TP5" at -40.796,1.871 h0.5
  text "TP5" at 9.004,1.871 h0.5
  text "TP5" at 58.804,1.871 h0.5
  text "TP4" at -87.127,1.721 h0.5
  text "TP4" at -37.327,1.721 h0.5
  text "TP4" at 12.473,1.721 h0.5
  text "TP4" at 62.273,1.721 h0.5
  text "TP10" at -80.696,-0.58 h0.5
  text "TP10" at -30.896,-0.58 h0.5
  text "TP10" at 18.904,-0.58 h0.5
  text "TP10" at 68.704,-0.58 h0.5
  text "TP17" at -90.596,-0.73 h0.5
  text "TP17" at -40.796,-0.73 h0.5
  text "TP17" at 9.004,-0.73 h0.5
  text "TP17" at 58.804,-0.73 h0.5
  text "TP11" at -79.774,-3.133 h0.5
  text "TP11" at -29.974,-3.133 h0.5
  text "TP11" at 19.826,-3.133 h0.5
  text "TP11" at 69.626,-3.133 h0.5
  text "TP13" at -81.546,-4.629 h0.5
  text "TP13" at -31.746,-4.629 h0.5
  text "TP13" at 18.054,-4.629 h0.5
  text "TP13" at 67.854,-4.629 h0.5
  text "TP9" at -78.295,-5.33 h0.5
  text "TP9" at -28.495,-5.33 h0.5
  text "TP9" at 21.305,-5.33 h0.5
  text "TP9" at 71.105,-5.33 h0.5
  text "TP3" at -88.445,-6.529 h0.5
  text "TP3" at -38.645,-6.529 h0.5
  text "TP3" at 11.155,-6.529 h0.5
  text "TP3" at 60.955,-6.529 h0.5
  text "TP18" at -97.995,-8.409 h0.5
  text "TP18" at -48.195,-8.409 h0.5
  text "TP18" at 1.605,-8.409 h0.5
  text "TP18" at 51.405,-8.409 h0.5
  text "TP1" at -88.397,-9.079 h0.5
  text "TP16" at -81.897,-9.079 h0.5
  text "TP1" at -38.597,-9.079 h0.5
  text "TP16" at -32.097,-9.079 h0.5
  text "TP1" at 11.203,-9.079 h0.5
  text "TP16" at 17.703,-9.079 h0.5
  text "TP1" at 61.003,-9.079 h0.5
  text "TP16" at 67.503,-9.079 h0.5
  text "TP19" at -100.147,-9.43 h0.5
  text "TP19" at -50.347,-9.43 h0.5
  text "TP19" at -0.547,-9.43 h0.5
  text "TP19" at 49.253,-9.43 h0.5
  text "TP20" at -102.806,-16.379 h0.5
  text "TP20" at -53.006,-16.379 h0.5
  text "TP20" at -3.206,-16.379 h0.5
  text "TP20" at 46.594,-16.379 h0.5
  text "TP12" at -80.195,-57.179 h0.5
  text "TP12" at -30.395,-57.179 h0.5
  text "TP12" at 19.405,-57.179 h0.5
  text "TP12" at 69.205,-57.179 h0.5
  text "TP2" at -88.046,-57.75 h0.5
  text "TP2" at -38.246,-57.75 h0.5
  text "TP2" at 11.554,-57.75 h0.5
  text "TP2" at 61.354,-57.75 h0.5
  text "TP8" at -90.546,-58.23 h0.5
  text "TP8" at -40.746,-58.23 h0.5
  text "TP8" at 9.054,-58.23 h0.5
  text "TP8" at 58.854,-58.23 h0.5
  text "TP15" at -79.796,-59.83 h0.5
  text "TP15" at -29.996,-59.83 h0.5
  text "TP15" at 19.804,-59.83 h0.5
  text "TP15" at 69.604,-59.83 h0.5
  text "TP6" at -87.127,-60.559 h0.5
  text "TP6" at -37.327,-60.559 h0.5
  text "TP6" at 12.473,-60.559 h0.5
  text "TP6" at 62.273,-60.559 h0.5
  text "TP7" at -89.657,-60.6 h0.5
  text "TP7" at -39.857,-60.6 h0.5
  text "TP7" at 9.943,-60.6 h0.5
  text "TP7" at 59.743,-60.6 h0.5
  text "TP14" at -79.796,-62.429 h0.5
  text "TP14" at -29.996,-62.429 h0.5
  text "TP14" at 19.804,-62.429 h0.5
  text "TP14" at 69.604,-62.429 h0.5
  text "TP5" at -90.596,-62.929 h0.5
  text "TP5" at -40.796,-62.929 h0.5
  text "TP5" at 9.004,-62.929 h0.5
  text "TP5" at 58.804,-62.929 h0.5
  text "TP4" at -87.127,-63.079 h0.5
  text "TP4" at -37.327,-63.079 h0.5
  text "TP4" at 12.473,-63.079 h0.5
  text "TP4" at 62.273,-63.079 h0.5
  text "TP10" at -80.696,-65.38 h0.5
  text "TP10" at -30.896,-65.38 h0.5
  text "TP10" at 18.904,-65.38 h0.5
  text "TP10" at 68.704,-65.38 h0.5
  text "TP17" at -90.596,-65.53 h0.5
  text "TP17" at -40.796,-65.53 h0.5
  text "TP17" at 9.004,-65.53 h0.5
  text "TP17" at 58.804,-65.53 h0.5
  text "TP11" at -79.774,-67.933 h0.5
  text "TP11" at -29.974,-67.933 h0.5
  text "TP11" at 19.826,-67.933 h0.5
  text "TP11" at 69.626,-67.933 h0.5
  text "TP13" at -81.546,-69.429 h0.5
  text "TP13" at -31.746,-69.429 h0.5
  text "TP13" at 18.054,-69.429 h0.5
  text "TP13" at 67.854,-69.429 h0.5
  text "TP9" at -78.295,-70.13 h0.5
  text "TP9" at -28.495,-70.13 h0.5
  text "TP9" at 21.305,-70.13 h0.5
  text "TP9" at 71.105,-70.13 h0.5
  text "TP3" at -88.445,-71.329 h0.5
  text "TP3" at -38.645,-71.329 h0.5
  text "TP3" at 11.155,-71.329 h0.5
  text "TP3" at 60.955,-71.329 h0.5
  text "TP18" at -97.995,-73.209 h0.5
  text "TP18" at -48.195,-73.209 h0.5
  text "TP18" at 1.605,-73.209 h0.5
  text "TP18" at 51.405,-73.209 h0.5
  text "TP1" at -88.397,-73.879 h0.5
  text "TP16" at -81.897,-73.879 h0.5
  text "TP1" at -38.597,-73.879 h0.5
  text "TP16" at -32.097,-73.879 h0.5
  text "TP1" at 11.203,-73.879 h0.5
  text "TP16" at 17.703,-73.879 h0.5
  text "TP1" at 61.003,-73.879 h0.5
  text "TP16" at 67.503,-73.879 h0.5
  text "TP19" at -100.147,-74.23 h0.5
  text "TP19" at -50.347,-74.23 h0.5
  text "TP19" at -0.547,-74.23 h0.5
  text "TP19" at 49.253,-74.23 h0.5
  text "TP20" at -102.806,-81.179 h0.5
  text "TP20" at -53.006,-81.179 h0.5
  text "TP20" at -3.206,-81.179 h0.5
  text "TP20" at 46.594,-81.179 h0.5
